VERSION 5.7 ;
BUSBITCHARS "[]" ;
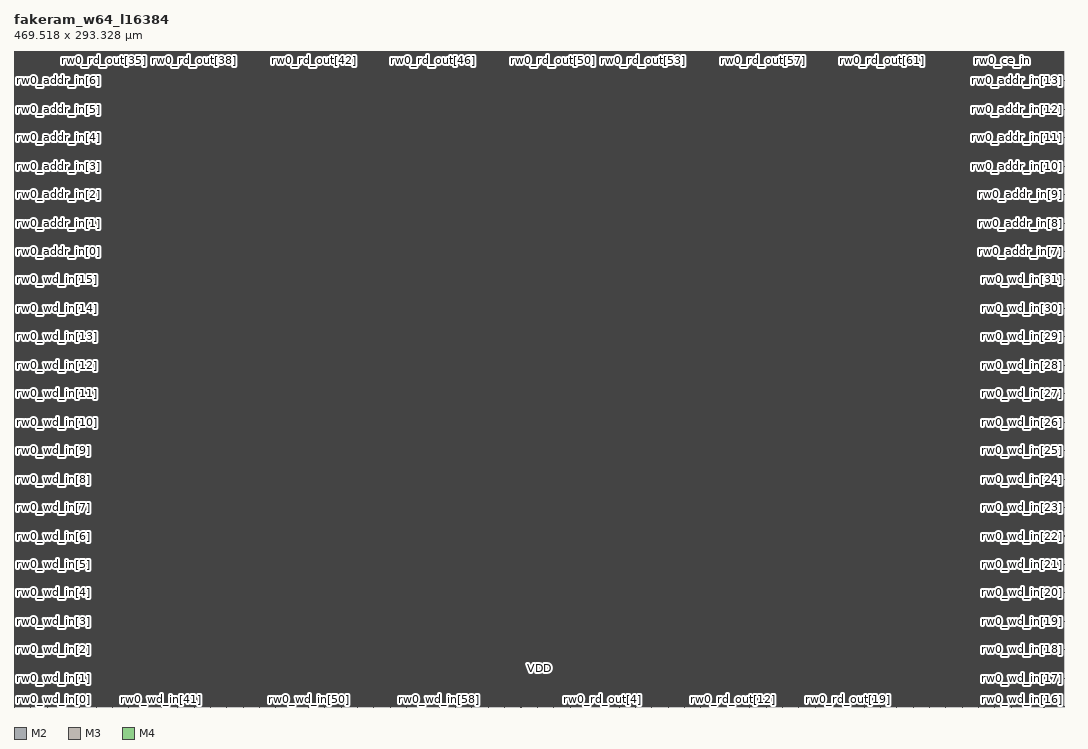
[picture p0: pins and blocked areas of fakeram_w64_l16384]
MACRO fakeram_w64_l16384
  FOREIGN fakeram_w64_l16384 0 0 ;
  SYMMETRY X Y R90 ;
  SIZE 469.518 BY 293.328 ;
  CLASS BLOCK ;
  PIN rw0_wd_in[0]
    DIRECTION INPUT ;
    USE SIGNAL ;
    SHAPE ABUTMENT ;
    PORT
      LAYER M2 ;
      RECT 0.000 0.138 0.036 0.150 ;
    END
  END rw0_wd_in[0]
  PIN rw0_wd_in[1]
    DIRECTION INPUT ;
    USE SIGNAL ;
    SHAPE ABUTMENT ;
    PORT
      LAYER M2 ;
      RECT 0.000 12.858 0.036 12.870 ;
    END
  END rw0_wd_in[1]
  PIN rw0_wd_in[2]
    DIRECTION INPUT ;
    USE SIGNAL ;
    SHAPE ABUTMENT ;
    PORT
      LAYER M2 ;
      RECT 0.000 25.578 0.036 25.590 ;
    END
  END rw0_wd_in[2]
  PIN rw0_wd_in[3]
    DIRECTION INPUT ;
    USE SIGNAL ;
    SHAPE ABUTMENT ;
    PORT
      LAYER M2 ;
      RECT 0.000 38.298 0.036 38.310 ;
    END
  END rw0_wd_in[3]
  PIN rw0_wd_in[4]
    DIRECTION INPUT ;
    USE SIGNAL ;
    SHAPE ABUTMENT ;
    PORT
      LAYER M2 ;
      RECT 0.000 51.018 0.036 51.030 ;
    END
  END rw0_wd_in[4]
  PIN rw0_wd_in[5]
    DIRECTION INPUT ;
    USE SIGNAL ;
    SHAPE ABUTMENT ;
    PORT
      LAYER M2 ;
      RECT 0.000 63.738 0.036 63.750 ;
    END
  END rw0_wd_in[5]
  PIN rw0_wd_in[6]
    DIRECTION INPUT ;
    USE SIGNAL ;
    SHAPE ABUTMENT ;
    PORT
      LAYER M2 ;
      RECT 0.000 76.458 0.036 76.470 ;
    END
  END rw0_wd_in[6]
  PIN rw0_wd_in[7]
    DIRECTION INPUT ;
    USE SIGNAL ;
    SHAPE ABUTMENT ;
    PORT
      LAYER M2 ;
      RECT 0.000 89.178 0.036 89.190 ;
    END
  END rw0_wd_in[7]
  PIN rw0_wd_in[8]
    DIRECTION INPUT ;
    USE SIGNAL ;
    SHAPE ABUTMENT ;
    PORT
      LAYER M2 ;
      RECT 0.000 101.898 0.036 101.910 ;
    END
  END rw0_wd_in[8]
  PIN rw0_wd_in[9]
    DIRECTION INPUT ;
    USE SIGNAL ;
    SHAPE ABUTMENT ;
    PORT
      LAYER M2 ;
      RECT 0.000 114.618 0.036 114.630 ;
    END
  END rw0_wd_in[9]
  PIN rw0_wd_in[10]
    DIRECTION INPUT ;
    USE SIGNAL ;
    SHAPE ABUTMENT ;
    PORT
      LAYER M2 ;
      RECT 0.000 127.338 0.036 127.350 ;
    END
  END rw0_wd_in[10]
  PIN rw0_wd_in[11]
    DIRECTION INPUT ;
    USE SIGNAL ;
    SHAPE ABUTMENT ;
    PORT
      LAYER M2 ;
      RECT 0.000 140.058 0.036 140.070 ;
    END
  END rw0_wd_in[11]
  PIN rw0_wd_in[12]
    DIRECTION INPUT ;
    USE SIGNAL ;
    SHAPE ABUTMENT ;
    PORT
      LAYER M2 ;
      RECT 0.000 152.778 0.036 152.790 ;
    END
  END rw0_wd_in[12]
  PIN rw0_wd_in[13]
    DIRECTION INPUT ;
    USE SIGNAL ;
    SHAPE ABUTMENT ;
    PORT
      LAYER M2 ;
      RECT 0.000 165.498 0.036 165.510 ;
    END
  END rw0_wd_in[13]
  PIN rw0_wd_in[14]
    DIRECTION INPUT ;
    USE SIGNAL ;
    SHAPE ABUTMENT ;
    PORT
      LAYER M2 ;
      RECT 0.000 178.218 0.036 178.230 ;
    END
  END rw0_wd_in[14]
  PIN rw0_wd_in[15]
    DIRECTION INPUT ;
    USE SIGNAL ;
    SHAPE ABUTMENT ;
    PORT
      LAYER M2 ;
      RECT 0.000 190.938 0.036 190.950 ;
    END
  END rw0_wd_in[15]
  PIN rw0_wd_in[16]
    DIRECTION INPUT ;
    USE SIGNAL ;
    SHAPE ABUTMENT ;
    PORT
      LAYER M2 ;
      RECT 469.482 0.138 469.518 0.150 ;
    END
  END rw0_wd_in[16]
  PIN rw0_wd_in[17]
    DIRECTION INPUT ;
    USE SIGNAL ;
    SHAPE ABUTMENT ;
    PORT
      LAYER M2 ;
      RECT 469.482 12.858 469.518 12.870 ;
    END
  END rw0_wd_in[17]
  PIN rw0_wd_in[18]
    DIRECTION INPUT ;
    USE SIGNAL ;
    SHAPE ABUTMENT ;
    PORT
      LAYER M2 ;
      RECT 469.482 25.578 469.518 25.590 ;
    END
  END rw0_wd_in[18]
  PIN rw0_wd_in[19]
    DIRECTION INPUT ;
    USE SIGNAL ;
    SHAPE ABUTMENT ;
    PORT
      LAYER M2 ;
      RECT 469.482 38.298 469.518 38.310 ;
    END
  END rw0_wd_in[19]
  PIN rw0_wd_in[20]
    DIRECTION INPUT ;
    USE SIGNAL ;
    SHAPE ABUTMENT ;
    PORT
      LAYER M2 ;
      RECT 469.482 51.018 469.518 51.030 ;
    END
  END rw0_wd_in[20]
  PIN rw0_wd_in[21]
    DIRECTION INPUT ;
    USE SIGNAL ;
    SHAPE ABUTMENT ;
    PORT
      LAYER M2 ;
      RECT 469.482 63.738 469.518 63.750 ;
    END
  END rw0_wd_in[21]
  PIN rw0_wd_in[22]
    DIRECTION INPUT ;
    USE SIGNAL ;
    SHAPE ABUTMENT ;
    PORT
      LAYER M2 ;
      RECT 469.482 76.458 469.518 76.470 ;
    END
  END rw0_wd_in[22]
  PIN rw0_wd_in[23]
    DIRECTION INPUT ;
    USE SIGNAL ;
    SHAPE ABUTMENT ;
    PORT
      LAYER M2 ;
      RECT 469.482 89.178 469.518 89.190 ;
    END
  END rw0_wd_in[23]
  PIN rw0_wd_in[24]
    DIRECTION INPUT ;
    USE SIGNAL ;
    SHAPE ABUTMENT ;
    PORT
      LAYER M2 ;
      RECT 469.482 101.898 469.518 101.910 ;
    END
  END rw0_wd_in[24]
  PIN rw0_wd_in[25]
    DIRECTION INPUT ;
    USE SIGNAL ;
    SHAPE ABUTMENT ;
    PORT
      LAYER M2 ;
      RECT 469.482 114.618 469.518 114.630 ;
    END
  END rw0_wd_in[25]
  PIN rw0_wd_in[26]
    DIRECTION INPUT ;
    USE SIGNAL ;
    SHAPE ABUTMENT ;
    PORT
      LAYER M2 ;
      RECT 469.482 127.338 469.518 127.350 ;
    END
  END rw0_wd_in[26]
  PIN rw0_wd_in[27]
    DIRECTION INPUT ;
    USE SIGNAL ;
    SHAPE ABUTMENT ;
    PORT
      LAYER M2 ;
      RECT 469.482 140.058 469.518 140.070 ;
    END
  END rw0_wd_in[27]
  PIN rw0_wd_in[28]
    DIRECTION INPUT ;
    USE SIGNAL ;
    SHAPE ABUTMENT ;
    PORT
      LAYER M2 ;
      RECT 469.482 152.778 469.518 152.790 ;
    END
  END rw0_wd_in[28]
  PIN rw0_wd_in[29]
    DIRECTION INPUT ;
    USE SIGNAL ;
    SHAPE ABUTMENT ;
    PORT
      LAYER M2 ;
      RECT 469.482 165.498 469.518 165.510 ;
    END
  END rw0_wd_in[29]
  PIN rw0_wd_in[30]
    DIRECTION INPUT ;
    USE SIGNAL ;
    SHAPE ABUTMENT ;
    PORT
      LAYER M2 ;
      RECT 469.482 178.218 469.518 178.230 ;
    END
  END rw0_wd_in[30]
  PIN rw0_wd_in[31]
    DIRECTION INPUT ;
    USE SIGNAL ;
    SHAPE ABUTMENT ;
    PORT
      LAYER M2 ;
      RECT 469.482 190.938 469.518 190.950 ;
    END
  END rw0_wd_in[31]
  PIN rw0_wd_in[32]
    DIRECTION INPUT ;
    USE SIGNAL ;
    SHAPE ABUTMENT ;
    PORT
      LAYER M3 ;
      RECT 0.161 0.000 0.175 0.042 ;
    END
  END rw0_wd_in[32]
  PIN rw0_wd_in[33]
    DIRECTION INPUT ;
    USE SIGNAL ;
    SHAPE ABUTMENT ;
    PORT
      LAYER M3 ;
      RECT 7.469 0.000 7.483 0.042 ;
    END
  END rw0_wd_in[33]
  PIN rw0_wd_in[34]
    DIRECTION INPUT ;
    USE SIGNAL ;
    SHAPE ABUTMENT ;
    PORT
      LAYER M3 ;
      RECT 14.777 0.000 14.791 0.042 ;
    END
  END rw0_wd_in[34]
  PIN rw0_wd_in[35]
    DIRECTION INPUT ;
    USE SIGNAL ;
    SHAPE ABUTMENT ;
    PORT
      LAYER M3 ;
      RECT 22.085 0.000 22.099 0.042 ;
    END
  END rw0_wd_in[35]
  PIN rw0_wd_in[36]
    DIRECTION INPUT ;
    USE SIGNAL ;
    SHAPE ABUTMENT ;
    PORT
      LAYER M3 ;
      RECT 29.393 0.000 29.407 0.042 ;
    END
  END rw0_wd_in[36]
  PIN rw0_wd_in[37]
    DIRECTION INPUT ;
    USE SIGNAL ;
    SHAPE ABUTMENT ;
    PORT
      LAYER M3 ;
      RECT 36.701 0.000 36.715 0.042 ;
    END
  END rw0_wd_in[37]
  PIN rw0_wd_in[38]
    DIRECTION INPUT ;
    USE SIGNAL ;
    SHAPE ABUTMENT ;
    PORT
      LAYER M3 ;
      RECT 44.009 0.000 44.023 0.042 ;
    END
  END rw0_wd_in[38]
  PIN rw0_wd_in[39]
    DIRECTION INPUT ;
    USE SIGNAL ;
    SHAPE ABUTMENT ;
    PORT
      LAYER M3 ;
      RECT 51.317 0.000 51.331 0.042 ;
    END
  END rw0_wd_in[39]
  PIN rw0_wd_in[40]
    DIRECTION INPUT ;
    USE SIGNAL ;
    SHAPE ABUTMENT ;
    PORT
      LAYER M3 ;
      RECT 58.625 0.000 58.639 0.042 ;
    END
  END rw0_wd_in[40]
  PIN rw0_wd_in[41]
    DIRECTION INPUT ;
    USE SIGNAL ;
    SHAPE ABUTMENT ;
    PORT
      LAYER M3 ;
      RECT 65.933 0.000 65.947 0.042 ;
    END
  END rw0_wd_in[41]
  PIN rw0_wd_in[42]
    DIRECTION INPUT ;
    USE SIGNAL ;
    SHAPE ABUTMENT ;
    PORT
      LAYER M3 ;
      RECT 73.241 0.000 73.255 0.042 ;
    END
  END rw0_wd_in[42]
  PIN rw0_wd_in[43]
    DIRECTION INPUT ;
    USE SIGNAL ;
    SHAPE ABUTMENT ;
    PORT
      LAYER M3 ;
      RECT 80.549 0.000 80.563 0.042 ;
    END
  END rw0_wd_in[43]
  PIN rw0_wd_in[44]
    DIRECTION INPUT ;
    USE SIGNAL ;
    SHAPE ABUTMENT ;
    PORT
      LAYER M3 ;
      RECT 87.857 0.000 87.871 0.042 ;
    END
  END rw0_wd_in[44]
  PIN rw0_wd_in[45]
    DIRECTION INPUT ;
    USE SIGNAL ;
    SHAPE ABUTMENT ;
    PORT
      LAYER M3 ;
      RECT 95.165 0.000 95.179 0.042 ;
    END
  END rw0_wd_in[45]
  PIN rw0_wd_in[46]
    DIRECTION INPUT ;
    USE SIGNAL ;
    SHAPE ABUTMENT ;
    PORT
      LAYER M3 ;
      RECT 102.473 0.000 102.487 0.042 ;
    END
  END rw0_wd_in[46]
  PIN rw0_wd_in[47]
    DIRECTION INPUT ;
    USE SIGNAL ;
    SHAPE ABUTMENT ;
    PORT
      LAYER M3 ;
      RECT 109.781 0.000 109.795 0.042 ;
    END
  END rw0_wd_in[47]
  PIN rw0_wd_in[48]
    DIRECTION INPUT ;
    USE SIGNAL ;
    SHAPE ABUTMENT ;
    PORT
      LAYER M3 ;
      RECT 117.089 0.000 117.103 0.042 ;
    END
  END rw0_wd_in[48]
  PIN rw0_wd_in[49]
    DIRECTION INPUT ;
    USE SIGNAL ;
    SHAPE ABUTMENT ;
    PORT
      LAYER M3 ;
      RECT 124.397 0.000 124.411 0.042 ;
    END
  END rw0_wd_in[49]
  PIN rw0_wd_in[50]
    DIRECTION INPUT ;
    USE SIGNAL ;
    SHAPE ABUTMENT ;
    PORT
      LAYER M3 ;
      RECT 131.705 0.000 131.719 0.042 ;
    END
  END rw0_wd_in[50]
  PIN rw0_wd_in[51]
    DIRECTION INPUT ;
    USE SIGNAL ;
    SHAPE ABUTMENT ;
    PORT
      LAYER M3 ;
      RECT 139.013 0.000 139.027 0.042 ;
    END
  END rw0_wd_in[51]
  PIN rw0_wd_in[52]
    DIRECTION INPUT ;
    USE SIGNAL ;
    SHAPE ABUTMENT ;
    PORT
      LAYER M3 ;
      RECT 146.321 0.000 146.335 0.042 ;
    END
  END rw0_wd_in[52]
  PIN rw0_wd_in[53]
    DIRECTION INPUT ;
    USE SIGNAL ;
    SHAPE ABUTMENT ;
    PORT
      LAYER M3 ;
      RECT 153.629 0.000 153.643 0.042 ;
    END
  END rw0_wd_in[53]
  PIN rw0_wd_in[54]
    DIRECTION INPUT ;
    USE SIGNAL ;
    SHAPE ABUTMENT ;
    PORT
      LAYER M3 ;
      RECT 160.937 0.000 160.951 0.042 ;
    END
  END rw0_wd_in[54]
  PIN rw0_wd_in[55]
    DIRECTION INPUT ;
    USE SIGNAL ;
    SHAPE ABUTMENT ;
    PORT
      LAYER M3 ;
      RECT 168.245 0.000 168.259 0.042 ;
    END
  END rw0_wd_in[55]
  PIN rw0_wd_in[56]
    DIRECTION INPUT ;
    USE SIGNAL ;
    SHAPE ABUTMENT ;
    PORT
      LAYER M3 ;
      RECT 175.553 0.000 175.567 0.042 ;
    END
  END rw0_wd_in[56]
  PIN rw0_wd_in[57]
    DIRECTION INPUT ;
    USE SIGNAL ;
    SHAPE ABUTMENT ;
    PORT
      LAYER M3 ;
      RECT 182.861 0.000 182.875 0.042 ;
    END
  END rw0_wd_in[57]
  PIN rw0_wd_in[58]
    DIRECTION INPUT ;
    USE SIGNAL ;
    SHAPE ABUTMENT ;
    PORT
      LAYER M3 ;
      RECT 190.169 0.000 190.183 0.042 ;
    END
  END rw0_wd_in[58]
  PIN rw0_wd_in[59]
    DIRECTION INPUT ;
    USE SIGNAL ;
    SHAPE ABUTMENT ;
    PORT
      LAYER M3 ;
      RECT 197.477 0.000 197.491 0.042 ;
    END
  END rw0_wd_in[59]
  PIN rw0_wd_in[60]
    DIRECTION INPUT ;
    USE SIGNAL ;
    SHAPE ABUTMENT ;
    PORT
      LAYER M3 ;
      RECT 204.785 0.000 204.799 0.042 ;
    END
  END rw0_wd_in[60]
  PIN rw0_wd_in[61]
    DIRECTION INPUT ;
    USE SIGNAL ;
    SHAPE ABUTMENT ;
    PORT
      LAYER M3 ;
      RECT 212.093 0.000 212.107 0.042 ;
    END
  END rw0_wd_in[61]
  PIN rw0_wd_in[62]
    DIRECTION INPUT ;
    USE SIGNAL ;
    SHAPE ABUTMENT ;
    PORT
      LAYER M3 ;
      RECT 219.401 0.000 219.415 0.042 ;
    END
  END rw0_wd_in[62]
  PIN rw0_wd_in[63]
    DIRECTION INPUT ;
    USE SIGNAL ;
    SHAPE ABUTMENT ;
    PORT
      LAYER M3 ;
      RECT 226.709 0.000 226.723 0.042 ;
    END
  END rw0_wd_in[63]
  PIN rw0_rd_out[0]
    DIRECTION OUTPUT ;
    USE SIGNAL ;
    SHAPE ABUTMENT ;
    PORT
      LAYER M3 ;
      RECT 234.017 0.000 234.031 0.042 ;
    END
  END rw0_rd_out[0]
  PIN rw0_rd_out[1]
    DIRECTION OUTPUT ;
    USE SIGNAL ;
    SHAPE ABUTMENT ;
    PORT
      LAYER M3 ;
      RECT 241.325 0.000 241.339 0.042 ;
    END
  END rw0_rd_out[1]
  PIN rw0_rd_out[2]
    DIRECTION OUTPUT ;
    USE SIGNAL ;
    SHAPE ABUTMENT ;
    PORT
      LAYER M3 ;
      RECT 248.633 0.000 248.647 0.042 ;
    END
  END rw0_rd_out[2]
  PIN rw0_rd_out[3]
    DIRECTION OUTPUT ;
    USE SIGNAL ;
    SHAPE ABUTMENT ;
    PORT
      LAYER M3 ;
      RECT 255.941 0.000 255.955 0.042 ;
    END
  END rw0_rd_out[3]
  PIN rw0_rd_out[4]
    DIRECTION OUTPUT ;
    USE SIGNAL ;
    SHAPE ABUTMENT ;
    PORT
      LAYER M3 ;
      RECT 263.249 0.000 263.263 0.042 ;
    END
  END rw0_rd_out[4]
  PIN rw0_rd_out[5]
    DIRECTION OUTPUT ;
    USE SIGNAL ;
    SHAPE ABUTMENT ;
    PORT
      LAYER M3 ;
      RECT 270.557 0.000 270.571 0.042 ;
    END
  END rw0_rd_out[5]
  PIN rw0_rd_out[6]
    DIRECTION OUTPUT ;
    USE SIGNAL ;
    SHAPE ABUTMENT ;
    PORT
      LAYER M3 ;
      RECT 277.865 0.000 277.879 0.042 ;
    END
  END rw0_rd_out[6]
  PIN rw0_rd_out[7]
    DIRECTION OUTPUT ;
    USE SIGNAL ;
    SHAPE ABUTMENT ;
    PORT
      LAYER M3 ;
      RECT 285.173 0.000 285.187 0.042 ;
    END
  END rw0_rd_out[7]
  PIN rw0_rd_out[8]
    DIRECTION OUTPUT ;
    USE SIGNAL ;
    SHAPE ABUTMENT ;
    PORT
      LAYER M3 ;
      RECT 292.481 0.000 292.495 0.042 ;
    END
  END rw0_rd_out[8]
  PIN rw0_rd_out[9]
    DIRECTION OUTPUT ;
    USE SIGNAL ;
    SHAPE ABUTMENT ;
    PORT
      LAYER M3 ;
      RECT 299.789 0.000 299.803 0.042 ;
    END
  END rw0_rd_out[9]
  PIN rw0_rd_out[10]
    DIRECTION OUTPUT ;
    USE SIGNAL ;
    SHAPE ABUTMENT ;
    PORT
      LAYER M3 ;
      RECT 307.097 0.000 307.111 0.042 ;
    END
  END rw0_rd_out[10]
  PIN rw0_rd_out[11]
    DIRECTION OUTPUT ;
    USE SIGNAL ;
    SHAPE ABUTMENT ;
    PORT
      LAYER M3 ;
      RECT 314.405 0.000 314.419 0.042 ;
    END
  END rw0_rd_out[11]
  PIN rw0_rd_out[12]
    DIRECTION OUTPUT ;
    USE SIGNAL ;
    SHAPE ABUTMENT ;
    PORT
      LAYER M3 ;
      RECT 321.713 0.000 321.727 0.042 ;
    END
  END rw0_rd_out[12]
  PIN rw0_rd_out[13]
    DIRECTION OUTPUT ;
    USE SIGNAL ;
    SHAPE ABUTMENT ;
    PORT
      LAYER M3 ;
      RECT 329.021 0.000 329.035 0.042 ;
    END
  END rw0_rd_out[13]
  PIN rw0_rd_out[14]
    DIRECTION OUTPUT ;
    USE SIGNAL ;
    SHAPE ABUTMENT ;
    PORT
      LAYER M3 ;
      RECT 336.329 0.000 336.343 0.042 ;
    END
  END rw0_rd_out[14]
  PIN rw0_rd_out[15]
    DIRECTION OUTPUT ;
    USE SIGNAL ;
    SHAPE ABUTMENT ;
    PORT
      LAYER M3 ;
      RECT 343.637 0.000 343.651 0.042 ;
    END
  END rw0_rd_out[15]
  PIN rw0_rd_out[16]
    DIRECTION OUTPUT ;
    USE SIGNAL ;
    SHAPE ABUTMENT ;
    PORT
      LAYER M3 ;
      RECT 350.945 0.000 350.959 0.042 ;
    END
  END rw0_rd_out[16]
  PIN rw0_rd_out[17]
    DIRECTION OUTPUT ;
    USE SIGNAL ;
    SHAPE ABUTMENT ;
    PORT
      LAYER M3 ;
      RECT 358.253 0.000 358.267 0.042 ;
    END
  END rw0_rd_out[17]
  PIN rw0_rd_out[18]
    DIRECTION OUTPUT ;
    USE SIGNAL ;
    SHAPE ABUTMENT ;
    PORT
      LAYER M3 ;
      RECT 365.561 0.000 365.575 0.042 ;
    END
  END rw0_rd_out[18]
  PIN rw0_rd_out[19]
    DIRECTION OUTPUT ;
    USE SIGNAL ;
    SHAPE ABUTMENT ;
    PORT
      LAYER M3 ;
      RECT 372.869 0.000 372.883 0.042 ;
    END
  END rw0_rd_out[19]
  PIN rw0_rd_out[20]
    DIRECTION OUTPUT ;
    USE SIGNAL ;
    SHAPE ABUTMENT ;
    PORT
      LAYER M3 ;
      RECT 380.177 0.000 380.191 0.042 ;
    END
  END rw0_rd_out[20]
  PIN rw0_rd_out[21]
    DIRECTION OUTPUT ;
    USE SIGNAL ;
    SHAPE ABUTMENT ;
    PORT
      LAYER M3 ;
      RECT 387.485 0.000 387.499 0.042 ;
    END
  END rw0_rd_out[21]
  PIN rw0_rd_out[22]
    DIRECTION OUTPUT ;
    USE SIGNAL ;
    SHAPE ABUTMENT ;
    PORT
      LAYER M3 ;
      RECT 394.793 0.000 394.807 0.042 ;
    END
  END rw0_rd_out[22]
  PIN rw0_rd_out[23]
    DIRECTION OUTPUT ;
    USE SIGNAL ;
    SHAPE ABUTMENT ;
    PORT
      LAYER M3 ;
      RECT 402.101 0.000 402.115 0.042 ;
    END
  END rw0_rd_out[23]
  PIN rw0_rd_out[24]
    DIRECTION OUTPUT ;
    USE SIGNAL ;
    SHAPE ABUTMENT ;
    PORT
      LAYER M3 ;
      RECT 409.409 0.000 409.423 0.042 ;
    END
  END rw0_rd_out[24]
  PIN rw0_rd_out[25]
    DIRECTION OUTPUT ;
    USE SIGNAL ;
    SHAPE ABUTMENT ;
    PORT
      LAYER M3 ;
      RECT 416.717 0.000 416.731 0.042 ;
    END
  END rw0_rd_out[25]
  PIN rw0_rd_out[26]
    DIRECTION OUTPUT ;
    USE SIGNAL ;
    SHAPE ABUTMENT ;
    PORT
      LAYER M3 ;
      RECT 424.025 0.000 424.039 0.042 ;
    END
  END rw0_rd_out[26]
  PIN rw0_rd_out[27]
    DIRECTION OUTPUT ;
    USE SIGNAL ;
    SHAPE ABUTMENT ;
    PORT
      LAYER M3 ;
      RECT 431.333 0.000 431.347 0.042 ;
    END
  END rw0_rd_out[27]
  PIN rw0_rd_out[28]
    DIRECTION OUTPUT ;
    USE SIGNAL ;
    SHAPE ABUTMENT ;
    PORT
      LAYER M3 ;
      RECT 438.641 0.000 438.655 0.042 ;
    END
  END rw0_rd_out[28]
  PIN rw0_rd_out[29]
    DIRECTION OUTPUT ;
    USE SIGNAL ;
    SHAPE ABUTMENT ;
    PORT
      LAYER M3 ;
      RECT 445.949 0.000 445.963 0.042 ;
    END
  END rw0_rd_out[29]
  PIN rw0_rd_out[30]
    DIRECTION OUTPUT ;
    USE SIGNAL ;
    SHAPE ABUTMENT ;
    PORT
      LAYER M3 ;
      RECT 453.257 0.000 453.271 0.042 ;
    END
  END rw0_rd_out[30]
  PIN rw0_rd_out[31]
    DIRECTION OUTPUT ;
    USE SIGNAL ;
    SHAPE ABUTMENT ;
    PORT
      LAYER M3 ;
      RECT 460.565 0.000 460.579 0.042 ;
    END
  END rw0_rd_out[31]
  PIN rw0_rd_out[32]
    DIRECTION OUTPUT ;
    USE SIGNAL ;
    SHAPE ABUTMENT ;
    PORT
      LAYER M3 ;
      RECT 0.161 293.286 0.175 293.328 ;
    END
  END rw0_rd_out[32]
  PIN rw0_rd_out[33]
    DIRECTION OUTPUT ;
    USE SIGNAL ;
    SHAPE ABUTMENT ;
    PORT
      LAYER M3 ;
      RECT 13.545 293.286 13.559 293.328 ;
    END
  END rw0_rd_out[33]
  PIN rw0_rd_out[34]
    DIRECTION OUTPUT ;
    USE SIGNAL ;
    SHAPE ABUTMENT ;
    PORT
      LAYER M3 ;
      RECT 26.929 293.286 26.943 293.328 ;
    END
  END rw0_rd_out[34]
  PIN rw0_rd_out[35]
    DIRECTION OUTPUT ;
    USE SIGNAL ;
    SHAPE ABUTMENT ;
    PORT
      LAYER M3 ;
      RECT 40.313 293.286 40.327 293.328 ;
    END
  END rw0_rd_out[35]
  PIN rw0_rd_out[36]
    DIRECTION OUTPUT ;
    USE SIGNAL ;
    SHAPE ABUTMENT ;
    PORT
      LAYER M3 ;
      RECT 53.697 293.286 53.711 293.328 ;
    END
  END rw0_rd_out[36]
  PIN rw0_rd_out[37]
    DIRECTION OUTPUT ;
    USE SIGNAL ;
    SHAPE ABUTMENT ;
    PORT
      LAYER M3 ;
      RECT 67.081 293.286 67.095 293.328 ;
    END
  END rw0_rd_out[37]
  PIN rw0_rd_out[38]
    DIRECTION OUTPUT ;
    USE SIGNAL ;
    SHAPE ABUTMENT ;
    PORT
      LAYER M3 ;
      RECT 80.465 293.286 80.479 293.328 ;
    END
  END rw0_rd_out[38]
  PIN rw0_rd_out[39]
    DIRECTION OUTPUT ;
    USE SIGNAL ;
    SHAPE ABUTMENT ;
    PORT
      LAYER M3 ;
      RECT 93.849 293.286 93.863 293.328 ;
    END
  END rw0_rd_out[39]
  PIN rw0_rd_out[40]
    DIRECTION OUTPUT ;
    USE SIGNAL ;
    SHAPE ABUTMENT ;
    PORT
      LAYER M3 ;
      RECT 107.233 293.286 107.247 293.328 ;
    END
  END rw0_rd_out[40]
  PIN rw0_rd_out[41]
    DIRECTION OUTPUT ;
    USE SIGNAL ;
    SHAPE ABUTMENT ;
    PORT
      LAYER M3 ;
      RECT 120.617 293.286 120.631 293.328 ;
    END
  END rw0_rd_out[41]
  PIN rw0_rd_out[42]
    DIRECTION OUTPUT ;
    USE SIGNAL ;
    SHAPE ABUTMENT ;
    PORT
      LAYER M3 ;
      RECT 134.001 293.286 134.015 293.328 ;
    END
  END rw0_rd_out[42]
  PIN rw0_rd_out[43]
    DIRECTION OUTPUT ;
    USE SIGNAL ;
    SHAPE ABUTMENT ;
    PORT
      LAYER M3 ;
      RECT 147.385 293.286 147.399 293.328 ;
    END
  END rw0_rd_out[43]
  PIN rw0_rd_out[44]
    DIRECTION OUTPUT ;
    USE SIGNAL ;
    SHAPE ABUTMENT ;
    PORT
      LAYER M3 ;
      RECT 160.769 293.286 160.783 293.328 ;
    END
  END rw0_rd_out[44]
  PIN rw0_rd_out[45]
    DIRECTION OUTPUT ;
    USE SIGNAL ;
    SHAPE ABUTMENT ;
    PORT
      LAYER M3 ;
      RECT 174.153 293.286 174.167 293.328 ;
    END
  END rw0_rd_out[45]
  PIN rw0_rd_out[46]
    DIRECTION OUTPUT ;
    USE SIGNAL ;
    SHAPE ABUTMENT ;
    PORT
      LAYER M3 ;
      RECT 187.537 293.286 187.551 293.328 ;
    END
  END rw0_rd_out[46]
  PIN rw0_rd_out[47]
    DIRECTION OUTPUT ;
    USE SIGNAL ;
    SHAPE ABUTMENT ;
    PORT
      LAYER M3 ;
      RECT 200.921 293.286 200.935 293.328 ;
    END
  END rw0_rd_out[47]
  PIN rw0_rd_out[48]
    DIRECTION OUTPUT ;
    USE SIGNAL ;
    SHAPE ABUTMENT ;
    PORT
      LAYER M3 ;
      RECT 214.305 293.286 214.319 293.328 ;
    END
  END rw0_rd_out[48]
  PIN rw0_rd_out[49]
    DIRECTION OUTPUT ;
    USE SIGNAL ;
    SHAPE ABUTMENT ;
    PORT
      LAYER M3 ;
      RECT 227.689 293.286 227.703 293.328 ;
    END
  END rw0_rd_out[49]
  PIN rw0_rd_out[50]
    DIRECTION OUTPUT ;
    USE SIGNAL ;
    SHAPE ABUTMENT ;
    PORT
      LAYER M3 ;
      RECT 241.073 293.286 241.087 293.328 ;
    END
  END rw0_rd_out[50]
  PIN rw0_rd_out[51]
    DIRECTION OUTPUT ;
    USE SIGNAL ;
    SHAPE ABUTMENT ;
    PORT
      LAYER M3 ;
      RECT 254.457 293.286 254.471 293.328 ;
    END
  END rw0_rd_out[51]
  PIN rw0_rd_out[52]
    DIRECTION OUTPUT ;
    USE SIGNAL ;
    SHAPE ABUTMENT ;
    PORT
      LAYER M3 ;
      RECT 267.841 293.286 267.855 293.328 ;
    END
  END rw0_rd_out[52]
  PIN rw0_rd_out[53]
    DIRECTION OUTPUT ;
    USE SIGNAL ;
    SHAPE ABUTMENT ;
    PORT
      LAYER M3 ;
      RECT 281.225 293.286 281.239 293.328 ;
    END
  END rw0_rd_out[53]
  PIN rw0_rd_out[54]
    DIRECTION OUTPUT ;
    USE SIGNAL ;
    SHAPE ABUTMENT ;
    PORT
      LAYER M3 ;
      RECT 294.609 293.286 294.623 293.328 ;
    END
  END rw0_rd_out[54]
  PIN rw0_rd_out[55]
    DIRECTION OUTPUT ;
    USE SIGNAL ;
    SHAPE ABUTMENT ;
    PORT
      LAYER M3 ;
      RECT 307.993 293.286 308.007 293.328 ;
    END
  END rw0_rd_out[55]
  PIN rw0_rd_out[56]
    DIRECTION OUTPUT ;
    USE SIGNAL ;
    SHAPE ABUTMENT ;
    PORT
      LAYER M3 ;
      RECT 321.377 293.286 321.391 293.328 ;
    END
  END rw0_rd_out[56]
  PIN rw0_rd_out[57]
    DIRECTION OUTPUT ;
    USE SIGNAL ;
    SHAPE ABUTMENT ;
    PORT
      LAYER M3 ;
      RECT 334.761 293.286 334.775 293.328 ;
    END
  END rw0_rd_out[57]
  PIN rw0_rd_out[58]
    DIRECTION OUTPUT ;
    USE SIGNAL ;
    SHAPE ABUTMENT ;
    PORT
      LAYER M3 ;
      RECT 348.145 293.286 348.159 293.328 ;
    END
  END rw0_rd_out[58]
  PIN rw0_rd_out[59]
    DIRECTION OUTPUT ;
    USE SIGNAL ;
    SHAPE ABUTMENT ;
    PORT
      LAYER M3 ;
      RECT 361.529 293.286 361.543 293.328 ;
    END
  END rw0_rd_out[59]
  PIN rw0_rd_out[60]
    DIRECTION OUTPUT ;
    USE SIGNAL ;
    SHAPE ABUTMENT ;
    PORT
      LAYER M3 ;
      RECT 374.913 293.286 374.927 293.328 ;
    END
  END rw0_rd_out[60]
  PIN rw0_rd_out[61]
    DIRECTION OUTPUT ;
    USE SIGNAL ;
    SHAPE ABUTMENT ;
    PORT
      LAYER M3 ;
      RECT 388.297 293.286 388.311 293.328 ;
    END
  END rw0_rd_out[61]
  PIN rw0_rd_out[62]
    DIRECTION OUTPUT ;
    USE SIGNAL ;
    SHAPE ABUTMENT ;
    PORT
      LAYER M3 ;
      RECT 401.681 293.286 401.695 293.328 ;
    END
  END rw0_rd_out[62]
  PIN rw0_rd_out[63]
    DIRECTION OUTPUT ;
    USE SIGNAL ;
    SHAPE ABUTMENT ;
    PORT
      LAYER M3 ;
      RECT 415.065 293.286 415.079 293.328 ;
    END
  END rw0_rd_out[63]
  PIN rw0_addr_in[0]
    DIRECTION INPUT ;
    USE SIGNAL ;
    SHAPE ABUTMENT ;
    PORT
      LAYER M2 ;
      RECT 0.000 203.658 0.036 203.670 ;
    END
  END rw0_addr_in[0]
  PIN rw0_addr_in[1]
    DIRECTION INPUT ;
    USE SIGNAL ;
    SHAPE ABUTMENT ;
    PORT
      LAYER M2 ;
      RECT 0.000 216.378 0.036 216.390 ;
    END
  END rw0_addr_in[1]
  PIN rw0_addr_in[2]
    DIRECTION INPUT ;
    USE SIGNAL ;
    SHAPE ABUTMENT ;
    PORT
      LAYER M2 ;
      RECT 0.000 229.098 0.036 229.110 ;
    END
  END rw0_addr_in[2]
  PIN rw0_addr_in[3]
    DIRECTION INPUT ;
    USE SIGNAL ;
    SHAPE ABUTMENT ;
    PORT
      LAYER M2 ;
      RECT 0.000 241.818 0.036 241.830 ;
    END
  END rw0_addr_in[3]
  PIN rw0_addr_in[4]
    DIRECTION INPUT ;
    USE SIGNAL ;
    SHAPE ABUTMENT ;
    PORT
      LAYER M2 ;
      RECT 0.000 254.538 0.036 254.550 ;
    END
  END rw0_addr_in[4]
  PIN rw0_addr_in[5]
    DIRECTION INPUT ;
    USE SIGNAL ;
    SHAPE ABUTMENT ;
    PORT
      LAYER M2 ;
      RECT 0.000 267.258 0.036 267.270 ;
    END
  END rw0_addr_in[5]
  PIN rw0_addr_in[6]
    DIRECTION INPUT ;
    USE SIGNAL ;
    SHAPE ABUTMENT ;
    PORT
      LAYER M2 ;
      RECT 0.000 279.978 0.036 279.990 ;
    END
  END rw0_addr_in[6]
  PIN rw0_addr_in[7]
    DIRECTION INPUT ;
    USE SIGNAL ;
    SHAPE ABUTMENT ;
    PORT
      LAYER M2 ;
      RECT 469.482 203.658 469.518 203.670 ;
    END
  END rw0_addr_in[7]
  PIN rw0_addr_in[8]
    DIRECTION INPUT ;
    USE SIGNAL ;
    SHAPE ABUTMENT ;
    PORT
      LAYER M2 ;
      RECT 469.482 216.378 469.518 216.390 ;
    END
  END rw0_addr_in[8]
  PIN rw0_addr_in[9]
    DIRECTION INPUT ;
    USE SIGNAL ;
    SHAPE ABUTMENT ;
    PORT
      LAYER M2 ;
      RECT 469.482 229.098 469.518 229.110 ;
    END
  END rw0_addr_in[9]
  PIN rw0_addr_in[10]
    DIRECTION INPUT ;
    USE SIGNAL ;
    SHAPE ABUTMENT ;
    PORT
      LAYER M2 ;
      RECT 469.482 241.818 469.518 241.830 ;
    END
  END rw0_addr_in[10]
  PIN rw0_addr_in[11]
    DIRECTION INPUT ;
    USE SIGNAL ;
    SHAPE ABUTMENT ;
    PORT
      LAYER M2 ;
      RECT 469.482 254.538 469.518 254.550 ;
    END
  END rw0_addr_in[11]
  PIN rw0_addr_in[12]
    DIRECTION INPUT ;
    USE SIGNAL ;
    SHAPE ABUTMENT ;
    PORT
      LAYER M2 ;
      RECT 469.482 267.258 469.518 267.270 ;
    END
  END rw0_addr_in[12]
  PIN rw0_addr_in[13]
    DIRECTION INPUT ;
    USE SIGNAL ;
    SHAPE ABUTMENT ;
    PORT
      LAYER M2 ;
      RECT 469.482 279.978 469.518 279.990 ;
    END
  END rw0_addr_in[13]
  PIN rw0_we_in
    DIRECTION INPUT ;
    USE SIGNAL ;
    SHAPE ABUTMENT ;
    PORT
      LAYER M3 ;
      RECT 428.449 293.286 428.463 293.328 ;
    END
  END rw0_we_in
  PIN rw0_ce_in
    DIRECTION INPUT ;
    USE SIGNAL ;
    SHAPE ABUTMENT ;
    PORT
      LAYER M3 ;
      RECT 441.833 293.286 441.847 293.328 ;
    END
  END rw0_ce_in
  PIN rw0_clk
    DIRECTION INPUT ;
    USE SIGNAL ;
    SHAPE ABUTMENT ;
    PORT
      LAYER M3 ;
      RECT 455.217 293.286 455.231 293.328 ;
    END
  END rw0_clk
  PIN VSS
    DIRECTION INOUT ;
    USE GROUND ;
    PORT
      LAYER M4 ;
      RECT 0.168 0.120 469.350 0.168 ;
      RECT 0.168 0.504 469.350 0.552 ;
      RECT 0.168 0.888 469.350 0.936 ;
      RECT 0.168 1.272 469.350 1.320 ;
      RECT 0.168 1.656 469.350 1.704 ;
      RECT 0.168 2.040 469.350 2.088 ;
      RECT 0.168 2.424 469.350 2.472 ;
      RECT 0.168 2.808 469.350 2.856 ;
      RECT 0.168 3.192 469.350 3.240 ;
      RECT 0.168 3.576 469.350 3.624 ;
      RECT 0.168 3.960 469.350 4.008 ;
      RECT 0.168 4.344 469.350 4.392 ;
      RECT 0.168 4.728 469.350 4.776 ;
      RECT 0.168 5.112 469.350 5.160 ;
      RECT 0.168 5.496 469.350 5.544 ;
      RECT 0.168 5.880 469.350 5.928 ;
      RECT 0.168 6.264 469.350 6.312 ;
      RECT 0.168 6.648 469.350 6.696 ;
      RECT 0.168 7.032 469.350 7.080 ;
      RECT 0.168 7.416 469.350 7.464 ;
      RECT 0.168 7.800 469.350 7.848 ;
      RECT 0.168 8.184 469.350 8.232 ;
      RECT 0.168 8.568 469.350 8.616 ;
      RECT 0.168 8.952 469.350 9.000 ;
      RECT 0.168 9.336 469.350 9.384 ;
      RECT 0.168 9.720 469.350 9.768 ;
      RECT 0.168 10.104 469.350 10.152 ;
      RECT 0.168 10.488 469.350 10.536 ;
      RECT 0.168 10.872 469.350 10.920 ;
      RECT 0.168 11.256 469.350 11.304 ;
      RECT 0.168 11.640 469.350 11.688 ;
      RECT 0.168 12.024 469.350 12.072 ;
      RECT 0.168 12.408 469.350 12.456 ;
      RECT 0.168 12.792 469.350 12.840 ;
      RECT 0.168 13.176 469.350 13.224 ;
      RECT 0.168 13.560 469.350 13.608 ;
      RECT 0.168 13.944 469.350 13.992 ;
      RECT 0.168 14.328 469.350 14.376 ;
      RECT 0.168 14.712 469.350 14.760 ;
      RECT 0.168 15.096 469.350 15.144 ;
      RECT 0.168 15.480 469.350 15.528 ;
      RECT 0.168 15.864 469.350 15.912 ;
      RECT 0.168 16.248 469.350 16.296 ;
      RECT 0.168 16.632 469.350 16.680 ;
      RECT 0.168 17.016 469.350 17.064 ;
      RECT 0.168 17.400 469.350 17.448 ;
      RECT 0.168 17.784 469.350 17.832 ;
      RECT 0.168 18.168 469.350 18.216 ;
      RECT 0.168 18.552 469.350 18.600 ;
      RECT 0.168 18.936 469.350 18.984 ;
      RECT 0.168 19.320 469.350 19.368 ;
      RECT 0.168 19.704 469.350 19.752 ;
      RECT 0.168 20.088 469.350 20.136 ;
      RECT 0.168 20.472 469.350 20.520 ;
      RECT 0.168 20.856 469.350 20.904 ;
      RECT 0.168 21.240 469.350 21.288 ;
      RECT 0.168 21.624 469.350 21.672 ;
      RECT 0.168 22.008 469.350 22.056 ;
      RECT 0.168 22.392 469.350 22.440 ;
      RECT 0.168 22.776 469.350 22.824 ;
      RECT 0.168 23.160 469.350 23.208 ;
      RECT 0.168 23.544 469.350 23.592 ;
      RECT 0.168 23.928 469.350 23.976 ;
      RECT 0.168 24.312 469.350 24.360 ;
      RECT 0.168 24.696 469.350 24.744 ;
      RECT 0.168 25.080 469.350 25.128 ;
      RECT 0.168 25.464 469.350 25.512 ;
      RECT 0.168 25.848 469.350 25.896 ;
      RECT 0.168 26.232 469.350 26.280 ;
      RECT 0.168 26.616 469.350 26.664 ;
      RECT 0.168 27.000 469.350 27.048 ;
      RECT 0.168 27.384 469.350 27.432 ;
      RECT 0.168 27.768 469.350 27.816 ;
      RECT 0.168 28.152 469.350 28.200 ;
      RECT 0.168 28.536 469.350 28.584 ;
      RECT 0.168 28.920 469.350 28.968 ;
      RECT 0.168 29.304 469.350 29.352 ;
      RECT 0.168 29.688 469.350 29.736 ;
      RECT 0.168 30.072 469.350 30.120 ;
      RECT 0.168 30.456 469.350 30.504 ;
      RECT 0.168 30.840 469.350 30.888 ;
      RECT 0.168 31.224 469.350 31.272 ;
      RECT 0.168 31.608 469.350 31.656 ;
      RECT 0.168 31.992 469.350 32.040 ;
      RECT 0.168 32.376 469.350 32.424 ;
      RECT 0.168 32.760 469.350 32.808 ;
      RECT 0.168 33.144 469.350 33.192 ;
      RECT 0.168 33.528 469.350 33.576 ;
      RECT 0.168 33.912 469.350 33.960 ;
      RECT 0.168 34.296 469.350 34.344 ;
      RECT 0.168 34.680 469.350 34.728 ;
      RECT 0.168 35.064 469.350 35.112 ;
      RECT 0.168 35.448 469.350 35.496 ;
      RECT 0.168 35.832 469.350 35.880 ;
      RECT 0.168 36.216 469.350 36.264 ;
      RECT 0.168 36.600 469.350 36.648 ;
      RECT 0.168 36.984 469.350 37.032 ;
      RECT 0.168 37.368 469.350 37.416 ;
      RECT 0.168 37.752 469.350 37.800 ;
      RECT 0.168 38.136 469.350 38.184 ;
      RECT 0.168 38.520 469.350 38.568 ;
      RECT 0.168 38.904 469.350 38.952 ;
      RECT 0.168 39.288 469.350 39.336 ;
      RECT 0.168 39.672 469.350 39.720 ;
      RECT 0.168 40.056 469.350 40.104 ;
      RECT 0.168 40.440 469.350 40.488 ;
      RECT 0.168 40.824 469.350 40.872 ;
      RECT 0.168 41.208 469.350 41.256 ;
      RECT 0.168 41.592 469.350 41.640 ;
      RECT 0.168 41.976 469.350 42.024 ;
      RECT 0.168 42.360 469.350 42.408 ;
      RECT 0.168 42.744 469.350 42.792 ;
      RECT 0.168 43.128 469.350 43.176 ;
      RECT 0.168 43.512 469.350 43.560 ;
      RECT 0.168 43.896 469.350 43.944 ;
      RECT 0.168 44.280 469.350 44.328 ;
      RECT 0.168 44.664 469.350 44.712 ;
      RECT 0.168 45.048 469.350 45.096 ;
      RECT 0.168 45.432 469.350 45.480 ;
      RECT 0.168 45.816 469.350 45.864 ;
      RECT 0.168 46.200 469.350 46.248 ;
      RECT 0.168 46.584 469.350 46.632 ;
      RECT 0.168 46.968 469.350 47.016 ;
      RECT 0.168 47.352 469.350 47.400 ;
      RECT 0.168 47.736 469.350 47.784 ;
      RECT 0.168 48.120 469.350 48.168 ;
      RECT 0.168 48.504 469.350 48.552 ;
      RECT 0.168 48.888 469.350 48.936 ;
      RECT 0.168 49.272 469.350 49.320 ;
      RECT 0.168 49.656 469.350 49.704 ;
      RECT 0.168 50.040 469.350 50.088 ;
      RECT 0.168 50.424 469.350 50.472 ;
      RECT 0.168 50.808 469.350 50.856 ;
      RECT 0.168 51.192 469.350 51.240 ;
      RECT 0.168 51.576 469.350 51.624 ;
      RECT 0.168 51.960 469.350 52.008 ;
      RECT 0.168 52.344 469.350 52.392 ;
      RECT 0.168 52.728 469.350 52.776 ;
      RECT 0.168 53.112 469.350 53.160 ;
      RECT 0.168 53.496 469.350 53.544 ;
      RECT 0.168 53.880 469.350 53.928 ;
      RECT 0.168 54.264 469.350 54.312 ;
      RECT 0.168 54.648 469.350 54.696 ;
      RECT 0.168 55.032 469.350 55.080 ;
      RECT 0.168 55.416 469.350 55.464 ;
      RECT 0.168 55.800 469.350 55.848 ;
      RECT 0.168 56.184 469.350 56.232 ;
      RECT 0.168 56.568 469.350 56.616 ;
      RECT 0.168 56.952 469.350 57.000 ;
      RECT 0.168 57.336 469.350 57.384 ;
      RECT 0.168 57.720 469.350 57.768 ;
      RECT 0.168 58.104 469.350 58.152 ;
      RECT 0.168 58.488 469.350 58.536 ;
      RECT 0.168 58.872 469.350 58.920 ;
      RECT 0.168 59.256 469.350 59.304 ;
      RECT 0.168 59.640 469.350 59.688 ;
      RECT 0.168 60.024 469.350 60.072 ;
      RECT 0.168 60.408 469.350 60.456 ;
      RECT 0.168 60.792 469.350 60.840 ;
      RECT 0.168 61.176 469.350 61.224 ;
      RECT 0.168 61.560 469.350 61.608 ;
      RECT 0.168 61.944 469.350 61.992 ;
      RECT 0.168 62.328 469.350 62.376 ;
      RECT 0.168 62.712 469.350 62.760 ;
      RECT 0.168 63.096 469.350 63.144 ;
      RECT 0.168 63.480 469.350 63.528 ;
      RECT 0.168 63.864 469.350 63.912 ;
      RECT 0.168 64.248 469.350 64.296 ;
      RECT 0.168 64.632 469.350 64.680 ;
      RECT 0.168 65.016 469.350 65.064 ;
      RECT 0.168 65.400 469.350 65.448 ;
      RECT 0.168 65.784 469.350 65.832 ;
      RECT 0.168 66.168 469.350 66.216 ;
      RECT 0.168 66.552 469.350 66.600 ;
      RECT 0.168 66.936 469.350 66.984 ;
      RECT 0.168 67.320 469.350 67.368 ;
      RECT 0.168 67.704 469.350 67.752 ;
      RECT 0.168 68.088 469.350 68.136 ;
      RECT 0.168 68.472 469.350 68.520 ;
      RECT 0.168 68.856 469.350 68.904 ;
      RECT 0.168 69.240 469.350 69.288 ;
      RECT 0.168 69.624 469.350 69.672 ;
      RECT 0.168 70.008 469.350 70.056 ;
      RECT 0.168 70.392 469.350 70.440 ;
      RECT 0.168 70.776 469.350 70.824 ;
      RECT 0.168 71.160 469.350 71.208 ;
      RECT 0.168 71.544 469.350 71.592 ;
      RECT 0.168 71.928 469.350 71.976 ;
      RECT 0.168 72.312 469.350 72.360 ;
      RECT 0.168 72.696 469.350 72.744 ;
      RECT 0.168 73.080 469.350 73.128 ;
      RECT 0.168 73.464 469.350 73.512 ;
      RECT 0.168 73.848 469.350 73.896 ;
      RECT 0.168 74.232 469.350 74.280 ;
      RECT 0.168 74.616 469.350 74.664 ;
      RECT 0.168 75.000 469.350 75.048 ;
      RECT 0.168 75.384 469.350 75.432 ;
      RECT 0.168 75.768 469.350 75.816 ;
      RECT 0.168 76.152 469.350 76.200 ;
      RECT 0.168 76.536 469.350 76.584 ;
      RECT 0.168 76.920 469.350 76.968 ;
      RECT 0.168 77.304 469.350 77.352 ;
      RECT 0.168 77.688 469.350 77.736 ;
      RECT 0.168 78.072 469.350 78.120 ;
      RECT 0.168 78.456 469.350 78.504 ;
      RECT 0.168 78.840 469.350 78.888 ;
      RECT 0.168 79.224 469.350 79.272 ;
      RECT 0.168 79.608 469.350 79.656 ;
      RECT 0.168 79.992 469.350 80.040 ;
      RECT 0.168 80.376 469.350 80.424 ;
      RECT 0.168 80.760 469.350 80.808 ;
      RECT 0.168 81.144 469.350 81.192 ;
      RECT 0.168 81.528 469.350 81.576 ;
      RECT 0.168 81.912 469.350 81.960 ;
      RECT 0.168 82.296 469.350 82.344 ;
      RECT 0.168 82.680 469.350 82.728 ;
      RECT 0.168 83.064 469.350 83.112 ;
      RECT 0.168 83.448 469.350 83.496 ;
      RECT 0.168 83.832 469.350 83.880 ;
      RECT 0.168 84.216 469.350 84.264 ;
      RECT 0.168 84.600 469.350 84.648 ;
      RECT 0.168 84.984 469.350 85.032 ;
      RECT 0.168 85.368 469.350 85.416 ;
      RECT 0.168 85.752 469.350 85.800 ;
      RECT 0.168 86.136 469.350 86.184 ;
      RECT 0.168 86.520 469.350 86.568 ;
      RECT 0.168 86.904 469.350 86.952 ;
      RECT 0.168 87.288 469.350 87.336 ;
      RECT 0.168 87.672 469.350 87.720 ;
      RECT 0.168 88.056 469.350 88.104 ;
      RECT 0.168 88.440 469.350 88.488 ;
      RECT 0.168 88.824 469.350 88.872 ;
      RECT 0.168 89.208 469.350 89.256 ;
      RECT 0.168 89.592 469.350 89.640 ;
      RECT 0.168 89.976 469.350 90.024 ;
      RECT 0.168 90.360 469.350 90.408 ;
      RECT 0.168 90.744 469.350 90.792 ;
      RECT 0.168 91.128 469.350 91.176 ;
      RECT 0.168 91.512 469.350 91.560 ;
      RECT 0.168 91.896 469.350 91.944 ;
      RECT 0.168 92.280 469.350 92.328 ;
      RECT 0.168 92.664 469.350 92.712 ;
      RECT 0.168 93.048 469.350 93.096 ;
      RECT 0.168 93.432 469.350 93.480 ;
      RECT 0.168 93.816 469.350 93.864 ;
      RECT 0.168 94.200 469.350 94.248 ;
      RECT 0.168 94.584 469.350 94.632 ;
      RECT 0.168 94.968 469.350 95.016 ;
      RECT 0.168 95.352 469.350 95.400 ;
      RECT 0.168 95.736 469.350 95.784 ;
      RECT 0.168 96.120 469.350 96.168 ;
      RECT 0.168 96.504 469.350 96.552 ;
      RECT 0.168 96.888 469.350 96.936 ;
      RECT 0.168 97.272 469.350 97.320 ;
      RECT 0.168 97.656 469.350 97.704 ;
      RECT 0.168 98.040 469.350 98.088 ;
      RECT 0.168 98.424 469.350 98.472 ;
      RECT 0.168 98.808 469.350 98.856 ;
      RECT 0.168 99.192 469.350 99.240 ;
      RECT 0.168 99.576 469.350 99.624 ;
      RECT 0.168 99.960 469.350 100.008 ;
      RECT 0.168 100.344 469.350 100.392 ;
      RECT 0.168 100.728 469.350 100.776 ;
      RECT 0.168 101.112 469.350 101.160 ;
      RECT 0.168 101.496 469.350 101.544 ;
      RECT 0.168 101.880 469.350 101.928 ;
      RECT 0.168 102.264 469.350 102.312 ;
      RECT 0.168 102.648 469.350 102.696 ;
      RECT 0.168 103.032 469.350 103.080 ;
      RECT 0.168 103.416 469.350 103.464 ;
      RECT 0.168 103.800 469.350 103.848 ;
      RECT 0.168 104.184 469.350 104.232 ;
      RECT 0.168 104.568 469.350 104.616 ;
      RECT 0.168 104.952 469.350 105.000 ;
      RECT 0.168 105.336 469.350 105.384 ;
      RECT 0.168 105.720 469.350 105.768 ;
      RECT 0.168 106.104 469.350 106.152 ;
      RECT 0.168 106.488 469.350 106.536 ;
      RECT 0.168 106.872 469.350 106.920 ;
      RECT 0.168 107.256 469.350 107.304 ;
      RECT 0.168 107.640 469.350 107.688 ;
      RECT 0.168 108.024 469.350 108.072 ;
      RECT 0.168 108.408 469.350 108.456 ;
      RECT 0.168 108.792 469.350 108.840 ;
      RECT 0.168 109.176 469.350 109.224 ;
      RECT 0.168 109.560 469.350 109.608 ;
      RECT 0.168 109.944 469.350 109.992 ;
      RECT 0.168 110.328 469.350 110.376 ;
      RECT 0.168 110.712 469.350 110.760 ;
      RECT 0.168 111.096 469.350 111.144 ;
      RECT 0.168 111.480 469.350 111.528 ;
      RECT 0.168 111.864 469.350 111.912 ;
      RECT 0.168 112.248 469.350 112.296 ;
      RECT 0.168 112.632 469.350 112.680 ;
      RECT 0.168 113.016 469.350 113.064 ;
      RECT 0.168 113.400 469.350 113.448 ;
      RECT 0.168 113.784 469.350 113.832 ;
      RECT 0.168 114.168 469.350 114.216 ;
      RECT 0.168 114.552 469.350 114.600 ;
      RECT 0.168 114.936 469.350 114.984 ;
      RECT 0.168 115.320 469.350 115.368 ;
      RECT 0.168 115.704 469.350 115.752 ;
      RECT 0.168 116.088 469.350 116.136 ;
      RECT 0.168 116.472 469.350 116.520 ;
      RECT 0.168 116.856 469.350 116.904 ;
      RECT 0.168 117.240 469.350 117.288 ;
      RECT 0.168 117.624 469.350 117.672 ;
      RECT 0.168 118.008 469.350 118.056 ;
      RECT 0.168 118.392 469.350 118.440 ;
      RECT 0.168 118.776 469.350 118.824 ;
      RECT 0.168 119.160 469.350 119.208 ;
      RECT 0.168 119.544 469.350 119.592 ;
      RECT 0.168 119.928 469.350 119.976 ;
      RECT 0.168 120.312 469.350 120.360 ;
      RECT 0.168 120.696 469.350 120.744 ;
      RECT 0.168 121.080 469.350 121.128 ;
      RECT 0.168 121.464 469.350 121.512 ;
      RECT 0.168 121.848 469.350 121.896 ;
      RECT 0.168 122.232 469.350 122.280 ;
      RECT 0.168 122.616 469.350 122.664 ;
      RECT 0.168 123.000 469.350 123.048 ;
      RECT 0.168 123.384 469.350 123.432 ;
      RECT 0.168 123.768 469.350 123.816 ;
      RECT 0.168 124.152 469.350 124.200 ;
      RECT 0.168 124.536 469.350 124.584 ;
      RECT 0.168 124.920 469.350 124.968 ;
      RECT 0.168 125.304 469.350 125.352 ;
      RECT 0.168 125.688 469.350 125.736 ;
      RECT 0.168 126.072 469.350 126.120 ;
      RECT 0.168 126.456 469.350 126.504 ;
      RECT 0.168 126.840 469.350 126.888 ;
      RECT 0.168 127.224 469.350 127.272 ;
      RECT 0.168 127.608 469.350 127.656 ;
      RECT 0.168 127.992 469.350 128.040 ;
      RECT 0.168 128.376 469.350 128.424 ;
      RECT 0.168 128.760 469.350 128.808 ;
      RECT 0.168 129.144 469.350 129.192 ;
      RECT 0.168 129.528 469.350 129.576 ;
      RECT 0.168 129.912 469.350 129.960 ;
      RECT 0.168 130.296 469.350 130.344 ;
      RECT 0.168 130.680 469.350 130.728 ;
      RECT 0.168 131.064 469.350 131.112 ;
      RECT 0.168 131.448 469.350 131.496 ;
      RECT 0.168 131.832 469.350 131.880 ;
      RECT 0.168 132.216 469.350 132.264 ;
      RECT 0.168 132.600 469.350 132.648 ;
      RECT 0.168 132.984 469.350 133.032 ;
      RECT 0.168 133.368 469.350 133.416 ;
      RECT 0.168 133.752 469.350 133.800 ;
      RECT 0.168 134.136 469.350 134.184 ;
      RECT 0.168 134.520 469.350 134.568 ;
      RECT 0.168 134.904 469.350 134.952 ;
      RECT 0.168 135.288 469.350 135.336 ;
      RECT 0.168 135.672 469.350 135.720 ;
      RECT 0.168 136.056 469.350 136.104 ;
      RECT 0.168 136.440 469.350 136.488 ;
      RECT 0.168 136.824 469.350 136.872 ;
      RECT 0.168 137.208 469.350 137.256 ;
      RECT 0.168 137.592 469.350 137.640 ;
      RECT 0.168 137.976 469.350 138.024 ;
      RECT 0.168 138.360 469.350 138.408 ;
      RECT 0.168 138.744 469.350 138.792 ;
      RECT 0.168 139.128 469.350 139.176 ;
      RECT 0.168 139.512 469.350 139.560 ;
      RECT 0.168 139.896 469.350 139.944 ;
      RECT 0.168 140.280 469.350 140.328 ;
      RECT 0.168 140.664 469.350 140.712 ;
      RECT 0.168 141.048 469.350 141.096 ;
      RECT 0.168 141.432 469.350 141.480 ;
      RECT 0.168 141.816 469.350 141.864 ;
      RECT 0.168 142.200 469.350 142.248 ;
      RECT 0.168 142.584 469.350 142.632 ;
      RECT 0.168 142.968 469.350 143.016 ;
      RECT 0.168 143.352 469.350 143.400 ;
      RECT 0.168 143.736 469.350 143.784 ;
      RECT 0.168 144.120 469.350 144.168 ;
      RECT 0.168 144.504 469.350 144.552 ;
      RECT 0.168 144.888 469.350 144.936 ;
      RECT 0.168 145.272 469.350 145.320 ;
      RECT 0.168 145.656 469.350 145.704 ;
      RECT 0.168 146.040 469.350 146.088 ;
      RECT 0.168 146.424 469.350 146.472 ;
      RECT 0.168 146.808 469.350 146.856 ;
      RECT 0.168 147.192 469.350 147.240 ;
      RECT 0.168 147.576 469.350 147.624 ;
      RECT 0.168 147.960 469.350 148.008 ;
      RECT 0.168 148.344 469.350 148.392 ;
      RECT 0.168 148.728 469.350 148.776 ;
      RECT 0.168 149.112 469.350 149.160 ;
      RECT 0.168 149.496 469.350 149.544 ;
      RECT 0.168 149.880 469.350 149.928 ;
      RECT 0.168 150.264 469.350 150.312 ;
      RECT 0.168 150.648 469.350 150.696 ;
      RECT 0.168 151.032 469.350 151.080 ;
      RECT 0.168 151.416 469.350 151.464 ;
      RECT 0.168 151.800 469.350 151.848 ;
      RECT 0.168 152.184 469.350 152.232 ;
      RECT 0.168 152.568 469.350 152.616 ;
      RECT 0.168 152.952 469.350 153.000 ;
      RECT 0.168 153.336 469.350 153.384 ;
      RECT 0.168 153.720 469.350 153.768 ;
      RECT 0.168 154.104 469.350 154.152 ;
      RECT 0.168 154.488 469.350 154.536 ;
      RECT 0.168 154.872 469.350 154.920 ;
      RECT 0.168 155.256 469.350 155.304 ;
      RECT 0.168 155.640 469.350 155.688 ;
      RECT 0.168 156.024 469.350 156.072 ;
      RECT 0.168 156.408 469.350 156.456 ;
      RECT 0.168 156.792 469.350 156.840 ;
      RECT 0.168 157.176 469.350 157.224 ;
      RECT 0.168 157.560 469.350 157.608 ;
      RECT 0.168 157.944 469.350 157.992 ;
      RECT 0.168 158.328 469.350 158.376 ;
      RECT 0.168 158.712 469.350 158.760 ;
      RECT 0.168 159.096 469.350 159.144 ;
      RECT 0.168 159.480 469.350 159.528 ;
      RECT 0.168 159.864 469.350 159.912 ;
      RECT 0.168 160.248 469.350 160.296 ;
      RECT 0.168 160.632 469.350 160.680 ;
      RECT 0.168 161.016 469.350 161.064 ;
      RECT 0.168 161.400 469.350 161.448 ;
      RECT 0.168 161.784 469.350 161.832 ;
      RECT 0.168 162.168 469.350 162.216 ;
      RECT 0.168 162.552 469.350 162.600 ;
      RECT 0.168 162.936 469.350 162.984 ;
      RECT 0.168 163.320 469.350 163.368 ;
      RECT 0.168 163.704 469.350 163.752 ;
      RECT 0.168 164.088 469.350 164.136 ;
      RECT 0.168 164.472 469.350 164.520 ;
      RECT 0.168 164.856 469.350 164.904 ;
      RECT 0.168 165.240 469.350 165.288 ;
      RECT 0.168 165.624 469.350 165.672 ;
      RECT 0.168 166.008 469.350 166.056 ;
      RECT 0.168 166.392 469.350 166.440 ;
      RECT 0.168 166.776 469.350 166.824 ;
      RECT 0.168 167.160 469.350 167.208 ;
      RECT 0.168 167.544 469.350 167.592 ;
      RECT 0.168 167.928 469.350 167.976 ;
      RECT 0.168 168.312 469.350 168.360 ;
      RECT 0.168 168.696 469.350 168.744 ;
      RECT 0.168 169.080 469.350 169.128 ;
      RECT 0.168 169.464 469.350 169.512 ;
      RECT 0.168 169.848 469.350 169.896 ;
      RECT 0.168 170.232 469.350 170.280 ;
      RECT 0.168 170.616 469.350 170.664 ;
      RECT 0.168 171.000 469.350 171.048 ;
      RECT 0.168 171.384 469.350 171.432 ;
      RECT 0.168 171.768 469.350 171.816 ;
      RECT 0.168 172.152 469.350 172.200 ;
      RECT 0.168 172.536 469.350 172.584 ;
      RECT 0.168 172.920 469.350 172.968 ;
      RECT 0.168 173.304 469.350 173.352 ;
      RECT 0.168 173.688 469.350 173.736 ;
      RECT 0.168 174.072 469.350 174.120 ;
      RECT 0.168 174.456 469.350 174.504 ;
      RECT 0.168 174.840 469.350 174.888 ;
      RECT 0.168 175.224 469.350 175.272 ;
      RECT 0.168 175.608 469.350 175.656 ;
      RECT 0.168 175.992 469.350 176.040 ;
      RECT 0.168 176.376 469.350 176.424 ;
      RECT 0.168 176.760 469.350 176.808 ;
      RECT 0.168 177.144 469.350 177.192 ;
      RECT 0.168 177.528 469.350 177.576 ;
      RECT 0.168 177.912 469.350 177.960 ;
      RECT 0.168 178.296 469.350 178.344 ;
      RECT 0.168 178.680 469.350 178.728 ;
      RECT 0.168 179.064 469.350 179.112 ;
      RECT 0.168 179.448 469.350 179.496 ;
      RECT 0.168 179.832 469.350 179.880 ;
      RECT 0.168 180.216 469.350 180.264 ;
      RECT 0.168 180.600 469.350 180.648 ;
      RECT 0.168 180.984 469.350 181.032 ;
      RECT 0.168 181.368 469.350 181.416 ;
      RECT 0.168 181.752 469.350 181.800 ;
      RECT 0.168 182.136 469.350 182.184 ;
      RECT 0.168 182.520 469.350 182.568 ;
      RECT 0.168 182.904 469.350 182.952 ;
      RECT 0.168 183.288 469.350 183.336 ;
      RECT 0.168 183.672 469.350 183.720 ;
      RECT 0.168 184.056 469.350 184.104 ;
      RECT 0.168 184.440 469.350 184.488 ;
      RECT 0.168 184.824 469.350 184.872 ;
      RECT 0.168 185.208 469.350 185.256 ;
      RECT 0.168 185.592 469.350 185.640 ;
      RECT 0.168 185.976 469.350 186.024 ;
      RECT 0.168 186.360 469.350 186.408 ;
      RECT 0.168 186.744 469.350 186.792 ;
      RECT 0.168 187.128 469.350 187.176 ;
      RECT 0.168 187.512 469.350 187.560 ;
      RECT 0.168 187.896 469.350 187.944 ;
      RECT 0.168 188.280 469.350 188.328 ;
      RECT 0.168 188.664 469.350 188.712 ;
      RECT 0.168 189.048 469.350 189.096 ;
      RECT 0.168 189.432 469.350 189.480 ;
      RECT 0.168 189.816 469.350 189.864 ;
      RECT 0.168 190.200 469.350 190.248 ;
      RECT 0.168 190.584 469.350 190.632 ;
      RECT 0.168 190.968 469.350 191.016 ;
      RECT 0.168 191.352 469.350 191.400 ;
      RECT 0.168 191.736 469.350 191.784 ;
      RECT 0.168 192.120 469.350 192.168 ;
      RECT 0.168 192.504 469.350 192.552 ;
      RECT 0.168 192.888 469.350 192.936 ;
      RECT 0.168 193.272 469.350 193.320 ;
      RECT 0.168 193.656 469.350 193.704 ;
      RECT 0.168 194.040 469.350 194.088 ;
      RECT 0.168 194.424 469.350 194.472 ;
      RECT 0.168 194.808 469.350 194.856 ;
      RECT 0.168 195.192 469.350 195.240 ;
      RECT 0.168 195.576 469.350 195.624 ;
      RECT 0.168 195.960 469.350 196.008 ;
      RECT 0.168 196.344 469.350 196.392 ;
      RECT 0.168 196.728 469.350 196.776 ;
      RECT 0.168 197.112 469.350 197.160 ;
      RECT 0.168 197.496 469.350 197.544 ;
      RECT 0.168 197.880 469.350 197.928 ;
      RECT 0.168 198.264 469.350 198.312 ;
      RECT 0.168 198.648 469.350 198.696 ;
      RECT 0.168 199.032 469.350 199.080 ;
      RECT 0.168 199.416 469.350 199.464 ;
      RECT 0.168 199.800 469.350 199.848 ;
      RECT 0.168 200.184 469.350 200.232 ;
      RECT 0.168 200.568 469.350 200.616 ;
      RECT 0.168 200.952 469.350 201.000 ;
      RECT 0.168 201.336 469.350 201.384 ;
      RECT 0.168 201.720 469.350 201.768 ;
      RECT 0.168 202.104 469.350 202.152 ;
      RECT 0.168 202.488 469.350 202.536 ;
      RECT 0.168 202.872 469.350 202.920 ;
      RECT 0.168 203.256 469.350 203.304 ;
      RECT 0.168 203.640 469.350 203.688 ;
      RECT 0.168 204.024 469.350 204.072 ;
      RECT 0.168 204.408 469.350 204.456 ;
      RECT 0.168 204.792 469.350 204.840 ;
      RECT 0.168 205.176 469.350 205.224 ;
      RECT 0.168 205.560 469.350 205.608 ;
      RECT 0.168 205.944 469.350 205.992 ;
      RECT 0.168 206.328 469.350 206.376 ;
      RECT 0.168 206.712 469.350 206.760 ;
      RECT 0.168 207.096 469.350 207.144 ;
      RECT 0.168 207.480 469.350 207.528 ;
      RECT 0.168 207.864 469.350 207.912 ;
      RECT 0.168 208.248 469.350 208.296 ;
      RECT 0.168 208.632 469.350 208.680 ;
      RECT 0.168 209.016 469.350 209.064 ;
      RECT 0.168 209.400 469.350 209.448 ;
      RECT 0.168 209.784 469.350 209.832 ;
      RECT 0.168 210.168 469.350 210.216 ;
      RECT 0.168 210.552 469.350 210.600 ;
      RECT 0.168 210.936 469.350 210.984 ;
      RECT 0.168 211.320 469.350 211.368 ;
      RECT 0.168 211.704 469.350 211.752 ;
      RECT 0.168 212.088 469.350 212.136 ;
      RECT 0.168 212.472 469.350 212.520 ;
      RECT 0.168 212.856 469.350 212.904 ;
      RECT 0.168 213.240 469.350 213.288 ;
      RECT 0.168 213.624 469.350 213.672 ;
      RECT 0.168 214.008 469.350 214.056 ;
      RECT 0.168 214.392 469.350 214.440 ;
      RECT 0.168 214.776 469.350 214.824 ;
      RECT 0.168 215.160 469.350 215.208 ;
      RECT 0.168 215.544 469.350 215.592 ;
      RECT 0.168 215.928 469.350 215.976 ;
      RECT 0.168 216.312 469.350 216.360 ;
      RECT 0.168 216.696 469.350 216.744 ;
      RECT 0.168 217.080 469.350 217.128 ;
      RECT 0.168 217.464 469.350 217.512 ;
      RECT 0.168 217.848 469.350 217.896 ;
      RECT 0.168 218.232 469.350 218.280 ;
      RECT 0.168 218.616 469.350 218.664 ;
      RECT 0.168 219.000 469.350 219.048 ;
      RECT 0.168 219.384 469.350 219.432 ;
      RECT 0.168 219.768 469.350 219.816 ;
      RECT 0.168 220.152 469.350 220.200 ;
      RECT 0.168 220.536 469.350 220.584 ;
      RECT 0.168 220.920 469.350 220.968 ;
      RECT 0.168 221.304 469.350 221.352 ;
      RECT 0.168 221.688 469.350 221.736 ;
      RECT 0.168 222.072 469.350 222.120 ;
      RECT 0.168 222.456 469.350 222.504 ;
      RECT 0.168 222.840 469.350 222.888 ;
      RECT 0.168 223.224 469.350 223.272 ;
      RECT 0.168 223.608 469.350 223.656 ;
      RECT 0.168 223.992 469.350 224.040 ;
      RECT 0.168 224.376 469.350 224.424 ;
      RECT 0.168 224.760 469.350 224.808 ;
      RECT 0.168 225.144 469.350 225.192 ;
      RECT 0.168 225.528 469.350 225.576 ;
      RECT 0.168 225.912 469.350 225.960 ;
      RECT 0.168 226.296 469.350 226.344 ;
      RECT 0.168 226.680 469.350 226.728 ;
      RECT 0.168 227.064 469.350 227.112 ;
      RECT 0.168 227.448 469.350 227.496 ;
      RECT 0.168 227.832 469.350 227.880 ;
      RECT 0.168 228.216 469.350 228.264 ;
      RECT 0.168 228.600 469.350 228.648 ;
      RECT 0.168 228.984 469.350 229.032 ;
      RECT 0.168 229.368 469.350 229.416 ;
      RECT 0.168 229.752 469.350 229.800 ;
      RECT 0.168 230.136 469.350 230.184 ;
      RECT 0.168 230.520 469.350 230.568 ;
      RECT 0.168 230.904 469.350 230.952 ;
      RECT 0.168 231.288 469.350 231.336 ;
      RECT 0.168 231.672 469.350 231.720 ;
      RECT 0.168 232.056 469.350 232.104 ;
      RECT 0.168 232.440 469.350 232.488 ;
      RECT 0.168 232.824 469.350 232.872 ;
      RECT 0.168 233.208 469.350 233.256 ;
      RECT 0.168 233.592 469.350 233.640 ;
      RECT 0.168 233.976 469.350 234.024 ;
      RECT 0.168 234.360 469.350 234.408 ;
      RECT 0.168 234.744 469.350 234.792 ;
      RECT 0.168 235.128 469.350 235.176 ;
      RECT 0.168 235.512 469.350 235.560 ;
      RECT 0.168 235.896 469.350 235.944 ;
      RECT 0.168 236.280 469.350 236.328 ;
      RECT 0.168 236.664 469.350 236.712 ;
      RECT 0.168 237.048 469.350 237.096 ;
      RECT 0.168 237.432 469.350 237.480 ;
      RECT 0.168 237.816 469.350 237.864 ;
      RECT 0.168 238.200 469.350 238.248 ;
      RECT 0.168 238.584 469.350 238.632 ;
      RECT 0.168 238.968 469.350 239.016 ;
      RECT 0.168 239.352 469.350 239.400 ;
      RECT 0.168 239.736 469.350 239.784 ;
      RECT 0.168 240.120 469.350 240.168 ;
      RECT 0.168 240.504 469.350 240.552 ;
      RECT 0.168 240.888 469.350 240.936 ;
      RECT 0.168 241.272 469.350 241.320 ;
      RECT 0.168 241.656 469.350 241.704 ;
      RECT 0.168 242.040 469.350 242.088 ;
      RECT 0.168 242.424 469.350 242.472 ;
      RECT 0.168 242.808 469.350 242.856 ;
      RECT 0.168 243.192 469.350 243.240 ;
      RECT 0.168 243.576 469.350 243.624 ;
      RECT 0.168 243.960 469.350 244.008 ;
      RECT 0.168 244.344 469.350 244.392 ;
      RECT 0.168 244.728 469.350 244.776 ;
      RECT 0.168 245.112 469.350 245.160 ;
      RECT 0.168 245.496 469.350 245.544 ;
      RECT 0.168 245.880 469.350 245.928 ;
      RECT 0.168 246.264 469.350 246.312 ;
      RECT 0.168 246.648 469.350 246.696 ;
      RECT 0.168 247.032 469.350 247.080 ;
      RECT 0.168 247.416 469.350 247.464 ;
      RECT 0.168 247.800 469.350 247.848 ;
      RECT 0.168 248.184 469.350 248.232 ;
      RECT 0.168 248.568 469.350 248.616 ;
      RECT 0.168 248.952 469.350 249.000 ;
      RECT 0.168 249.336 469.350 249.384 ;
      RECT 0.168 249.720 469.350 249.768 ;
      RECT 0.168 250.104 469.350 250.152 ;
      RECT 0.168 250.488 469.350 250.536 ;
      RECT 0.168 250.872 469.350 250.920 ;
      RECT 0.168 251.256 469.350 251.304 ;
      RECT 0.168 251.640 469.350 251.688 ;
      RECT 0.168 252.024 469.350 252.072 ;
      RECT 0.168 252.408 469.350 252.456 ;
      RECT 0.168 252.792 469.350 252.840 ;
      RECT 0.168 253.176 469.350 253.224 ;
      RECT 0.168 253.560 469.350 253.608 ;
      RECT 0.168 253.944 469.350 253.992 ;
      RECT 0.168 254.328 469.350 254.376 ;
      RECT 0.168 254.712 469.350 254.760 ;
      RECT 0.168 255.096 469.350 255.144 ;
      RECT 0.168 255.480 469.350 255.528 ;
      RECT 0.168 255.864 469.350 255.912 ;
      RECT 0.168 256.248 469.350 256.296 ;
      RECT 0.168 256.632 469.350 256.680 ;
      RECT 0.168 257.016 469.350 257.064 ;
      RECT 0.168 257.400 469.350 257.448 ;
      RECT 0.168 257.784 469.350 257.832 ;
      RECT 0.168 258.168 469.350 258.216 ;
      RECT 0.168 258.552 469.350 258.600 ;
      RECT 0.168 258.936 469.350 258.984 ;
      RECT 0.168 259.320 469.350 259.368 ;
      RECT 0.168 259.704 469.350 259.752 ;
      RECT 0.168 260.088 469.350 260.136 ;
      RECT 0.168 260.472 469.350 260.520 ;
      RECT 0.168 260.856 469.350 260.904 ;
      RECT 0.168 261.240 469.350 261.288 ;
      RECT 0.168 261.624 469.350 261.672 ;
      RECT 0.168 262.008 469.350 262.056 ;
      RECT 0.168 262.392 469.350 262.440 ;
      RECT 0.168 262.776 469.350 262.824 ;
      RECT 0.168 263.160 469.350 263.208 ;
      RECT 0.168 263.544 469.350 263.592 ;
      RECT 0.168 263.928 469.350 263.976 ;
      RECT 0.168 264.312 469.350 264.360 ;
      RECT 0.168 264.696 469.350 264.744 ;
      RECT 0.168 265.080 469.350 265.128 ;
      RECT 0.168 265.464 469.350 265.512 ;
      RECT 0.168 265.848 469.350 265.896 ;
      RECT 0.168 266.232 469.350 266.280 ;
      RECT 0.168 266.616 469.350 266.664 ;
      RECT 0.168 267.000 469.350 267.048 ;
      RECT 0.168 267.384 469.350 267.432 ;
      RECT 0.168 267.768 469.350 267.816 ;
      RECT 0.168 268.152 469.350 268.200 ;
      RECT 0.168 268.536 469.350 268.584 ;
      RECT 0.168 268.920 469.350 268.968 ;
      RECT 0.168 269.304 469.350 269.352 ;
      RECT 0.168 269.688 469.350 269.736 ;
      RECT 0.168 270.072 469.350 270.120 ;
      RECT 0.168 270.456 469.350 270.504 ;
      RECT 0.168 270.840 469.350 270.888 ;
      RECT 0.168 271.224 469.350 271.272 ;
      RECT 0.168 271.608 469.350 271.656 ;
      RECT 0.168 271.992 469.350 272.040 ;
      RECT 0.168 272.376 469.350 272.424 ;
      RECT 0.168 272.760 469.350 272.808 ;
      RECT 0.168 273.144 469.350 273.192 ;
      RECT 0.168 273.528 469.350 273.576 ;
      RECT 0.168 273.912 469.350 273.960 ;
      RECT 0.168 274.296 469.350 274.344 ;
      RECT 0.168 274.680 469.350 274.728 ;
      RECT 0.168 275.064 469.350 275.112 ;
      RECT 0.168 275.448 469.350 275.496 ;
      RECT 0.168 275.832 469.350 275.880 ;
      RECT 0.168 276.216 469.350 276.264 ;
      RECT 0.168 276.600 469.350 276.648 ;
      RECT 0.168 276.984 469.350 277.032 ;
      RECT 0.168 277.368 469.350 277.416 ;
      RECT 0.168 277.752 469.350 277.800 ;
      RECT 0.168 278.136 469.350 278.184 ;
      RECT 0.168 278.520 469.350 278.568 ;
      RECT 0.168 278.904 469.350 278.952 ;
      RECT 0.168 279.288 469.350 279.336 ;
      RECT 0.168 279.672 469.350 279.720 ;
      RECT 0.168 280.056 469.350 280.104 ;
      RECT 0.168 280.440 469.350 280.488 ;
      RECT 0.168 280.824 469.350 280.872 ;
      RECT 0.168 281.208 469.350 281.256 ;
      RECT 0.168 281.592 469.350 281.640 ;
      RECT 0.168 281.976 469.350 282.024 ;
      RECT 0.168 282.360 469.350 282.408 ;
      RECT 0.168 282.744 469.350 282.792 ;
      RECT 0.168 283.128 469.350 283.176 ;
      RECT 0.168 283.512 469.350 283.560 ;
      RECT 0.168 283.896 469.350 283.944 ;
      RECT 0.168 284.280 469.350 284.328 ;
      RECT 0.168 284.664 469.350 284.712 ;
      RECT 0.168 285.048 469.350 285.096 ;
      RECT 0.168 285.432 469.350 285.480 ;
      RECT 0.168 285.816 469.350 285.864 ;
      RECT 0.168 286.200 469.350 286.248 ;
      RECT 0.168 286.584 469.350 286.632 ;
      RECT 0.168 286.968 469.350 287.016 ;
      RECT 0.168 287.352 469.350 287.400 ;
      RECT 0.168 287.736 469.350 287.784 ;
      RECT 0.168 288.120 469.350 288.168 ;
      RECT 0.168 288.504 469.350 288.552 ;
      RECT 0.168 288.888 469.350 288.936 ;
      RECT 0.168 289.272 469.350 289.320 ;
      RECT 0.168 289.656 469.350 289.704 ;
      RECT 0.168 290.040 469.350 290.088 ;
      RECT 0.168 290.424 469.350 290.472 ;
      RECT 0.168 290.808 469.350 290.856 ;
      RECT 0.168 291.192 469.350 291.240 ;
      RECT 0.168 291.576 469.350 291.624 ;
      RECT 0.168 291.960 469.350 292.008 ;
      RECT 0.168 292.344 469.350 292.392 ;
      RECT 0.168 292.728 469.350 292.776 ;
      RECT 0.168 293.112 469.350 293.160 ;
    END
  END VSS
  PIN VDD
    DIRECTION INOUT ;
    USE POWER ;
    PORT
      LAYER M4 ;
      RECT 0.168 0.312 469.350 0.360 ;
      RECT 0.168 0.696 469.350 0.744 ;
      RECT 0.168 1.080 469.350 1.128 ;
      RECT 0.168 1.464 469.350 1.512 ;
      RECT 0.168 1.848 469.350 1.896 ;
      RECT 0.168 2.232 469.350 2.280 ;
      RECT 0.168 2.616 469.350 2.664 ;
      RECT 0.168 3.000 469.350 3.048 ;
      RECT 0.168 3.384 469.350 3.432 ;
      RECT 0.168 3.768 469.350 3.816 ;
      RECT 0.168 4.152 469.350 4.200 ;
      RECT 0.168 4.536 469.350 4.584 ;
      RECT 0.168 4.920 469.350 4.968 ;
      RECT 0.168 5.304 469.350 5.352 ;
      RECT 0.168 5.688 469.350 5.736 ;
      RECT 0.168 6.072 469.350 6.120 ;
      RECT 0.168 6.456 469.350 6.504 ;
      RECT 0.168 6.840 469.350 6.888 ;
      RECT 0.168 7.224 469.350 7.272 ;
      RECT 0.168 7.608 469.350 7.656 ;
      RECT 0.168 7.992 469.350 8.040 ;
      RECT 0.168 8.376 469.350 8.424 ;
      RECT 0.168 8.760 469.350 8.808 ;
      RECT 0.168 9.144 469.350 9.192 ;
      RECT 0.168 9.528 469.350 9.576 ;
      RECT 0.168 9.912 469.350 9.960 ;
      RECT 0.168 10.296 469.350 10.344 ;
      RECT 0.168 10.680 469.350 10.728 ;
      RECT 0.168 11.064 469.350 11.112 ;
      RECT 0.168 11.448 469.350 11.496 ;
      RECT 0.168 11.832 469.350 11.880 ;
      RECT 0.168 12.216 469.350 12.264 ;
      RECT 0.168 12.600 469.350 12.648 ;
      RECT 0.168 12.984 469.350 13.032 ;
      RECT 0.168 13.368 469.350 13.416 ;
      RECT 0.168 13.752 469.350 13.800 ;
      RECT 0.168 14.136 469.350 14.184 ;
      RECT 0.168 14.520 469.350 14.568 ;
      RECT 0.168 14.904 469.350 14.952 ;
      RECT 0.168 15.288 469.350 15.336 ;
      RECT 0.168 15.672 469.350 15.720 ;
      RECT 0.168 16.056 469.350 16.104 ;
      RECT 0.168 16.440 469.350 16.488 ;
      RECT 0.168 16.824 469.350 16.872 ;
      RECT 0.168 17.208 469.350 17.256 ;
      RECT 0.168 17.592 469.350 17.640 ;
      RECT 0.168 17.976 469.350 18.024 ;
      RECT 0.168 18.360 469.350 18.408 ;
      RECT 0.168 18.744 469.350 18.792 ;
      RECT 0.168 19.128 469.350 19.176 ;
      RECT 0.168 19.512 469.350 19.560 ;
      RECT 0.168 19.896 469.350 19.944 ;
      RECT 0.168 20.280 469.350 20.328 ;
      RECT 0.168 20.664 469.350 20.712 ;
      RECT 0.168 21.048 469.350 21.096 ;
      RECT 0.168 21.432 469.350 21.480 ;
      RECT 0.168 21.816 469.350 21.864 ;
      RECT 0.168 22.200 469.350 22.248 ;
      RECT 0.168 22.584 469.350 22.632 ;
      RECT 0.168 22.968 469.350 23.016 ;
      RECT 0.168 23.352 469.350 23.400 ;
      RECT 0.168 23.736 469.350 23.784 ;
      RECT 0.168 24.120 469.350 24.168 ;
      RECT 0.168 24.504 469.350 24.552 ;
      RECT 0.168 24.888 469.350 24.936 ;
      RECT 0.168 25.272 469.350 25.320 ;
      RECT 0.168 25.656 469.350 25.704 ;
      RECT 0.168 26.040 469.350 26.088 ;
      RECT 0.168 26.424 469.350 26.472 ;
      RECT 0.168 26.808 469.350 26.856 ;
      RECT 0.168 27.192 469.350 27.240 ;
      RECT 0.168 27.576 469.350 27.624 ;
      RECT 0.168 27.960 469.350 28.008 ;
      RECT 0.168 28.344 469.350 28.392 ;
      RECT 0.168 28.728 469.350 28.776 ;
      RECT 0.168 29.112 469.350 29.160 ;
      RECT 0.168 29.496 469.350 29.544 ;
      RECT 0.168 29.880 469.350 29.928 ;
      RECT 0.168 30.264 469.350 30.312 ;
      RECT 0.168 30.648 469.350 30.696 ;
      RECT 0.168 31.032 469.350 31.080 ;
      RECT 0.168 31.416 469.350 31.464 ;
      RECT 0.168 31.800 469.350 31.848 ;
      RECT 0.168 32.184 469.350 32.232 ;
      RECT 0.168 32.568 469.350 32.616 ;
      RECT 0.168 32.952 469.350 33.000 ;
      RECT 0.168 33.336 469.350 33.384 ;
      RECT 0.168 33.720 469.350 33.768 ;
      RECT 0.168 34.104 469.350 34.152 ;
      RECT 0.168 34.488 469.350 34.536 ;
      RECT 0.168 34.872 469.350 34.920 ;
      RECT 0.168 35.256 469.350 35.304 ;
      RECT 0.168 35.640 469.350 35.688 ;
      RECT 0.168 36.024 469.350 36.072 ;
      RECT 0.168 36.408 469.350 36.456 ;
      RECT 0.168 36.792 469.350 36.840 ;
      RECT 0.168 37.176 469.350 37.224 ;
      RECT 0.168 37.560 469.350 37.608 ;
      RECT 0.168 37.944 469.350 37.992 ;
      RECT 0.168 38.328 469.350 38.376 ;
      RECT 0.168 38.712 469.350 38.760 ;
      RECT 0.168 39.096 469.350 39.144 ;
      RECT 0.168 39.480 469.350 39.528 ;
      RECT 0.168 39.864 469.350 39.912 ;
      RECT 0.168 40.248 469.350 40.296 ;
      RECT 0.168 40.632 469.350 40.680 ;
      RECT 0.168 41.016 469.350 41.064 ;
      RECT 0.168 41.400 469.350 41.448 ;
      RECT 0.168 41.784 469.350 41.832 ;
      RECT 0.168 42.168 469.350 42.216 ;
      RECT 0.168 42.552 469.350 42.600 ;
      RECT 0.168 42.936 469.350 42.984 ;
      RECT 0.168 43.320 469.350 43.368 ;
      RECT 0.168 43.704 469.350 43.752 ;
      RECT 0.168 44.088 469.350 44.136 ;
      RECT 0.168 44.472 469.350 44.520 ;
      RECT 0.168 44.856 469.350 44.904 ;
      RECT 0.168 45.240 469.350 45.288 ;
      RECT 0.168 45.624 469.350 45.672 ;
      RECT 0.168 46.008 469.350 46.056 ;
      RECT 0.168 46.392 469.350 46.440 ;
      RECT 0.168 46.776 469.350 46.824 ;
      RECT 0.168 47.160 469.350 47.208 ;
      RECT 0.168 47.544 469.350 47.592 ;
      RECT 0.168 47.928 469.350 47.976 ;
      RECT 0.168 48.312 469.350 48.360 ;
      RECT 0.168 48.696 469.350 48.744 ;
      RECT 0.168 49.080 469.350 49.128 ;
      RECT 0.168 49.464 469.350 49.512 ;
      RECT 0.168 49.848 469.350 49.896 ;
      RECT 0.168 50.232 469.350 50.280 ;
      RECT 0.168 50.616 469.350 50.664 ;
      RECT 0.168 51.000 469.350 51.048 ;
      RECT 0.168 51.384 469.350 51.432 ;
      RECT 0.168 51.768 469.350 51.816 ;
      RECT 0.168 52.152 469.350 52.200 ;
      RECT 0.168 52.536 469.350 52.584 ;
      RECT 0.168 52.920 469.350 52.968 ;
      RECT 0.168 53.304 469.350 53.352 ;
      RECT 0.168 53.688 469.350 53.736 ;
      RECT 0.168 54.072 469.350 54.120 ;
      RECT 0.168 54.456 469.350 54.504 ;
      RECT 0.168 54.840 469.350 54.888 ;
      RECT 0.168 55.224 469.350 55.272 ;
      RECT 0.168 55.608 469.350 55.656 ;
      RECT 0.168 55.992 469.350 56.040 ;
      RECT 0.168 56.376 469.350 56.424 ;
      RECT 0.168 56.760 469.350 56.808 ;
      RECT 0.168 57.144 469.350 57.192 ;
      RECT 0.168 57.528 469.350 57.576 ;
      RECT 0.168 57.912 469.350 57.960 ;
      RECT 0.168 58.296 469.350 58.344 ;
      RECT 0.168 58.680 469.350 58.728 ;
      RECT 0.168 59.064 469.350 59.112 ;
      RECT 0.168 59.448 469.350 59.496 ;
      RECT 0.168 59.832 469.350 59.880 ;
      RECT 0.168 60.216 469.350 60.264 ;
      RECT 0.168 60.600 469.350 60.648 ;
      RECT 0.168 60.984 469.350 61.032 ;
      RECT 0.168 61.368 469.350 61.416 ;
      RECT 0.168 61.752 469.350 61.800 ;
      RECT 0.168 62.136 469.350 62.184 ;
      RECT 0.168 62.520 469.350 62.568 ;
      RECT 0.168 62.904 469.350 62.952 ;
      RECT 0.168 63.288 469.350 63.336 ;
      RECT 0.168 63.672 469.350 63.720 ;
      RECT 0.168 64.056 469.350 64.104 ;
      RECT 0.168 64.440 469.350 64.488 ;
      RECT 0.168 64.824 469.350 64.872 ;
      RECT 0.168 65.208 469.350 65.256 ;
      RECT 0.168 65.592 469.350 65.640 ;
      RECT 0.168 65.976 469.350 66.024 ;
      RECT 0.168 66.360 469.350 66.408 ;
      RECT 0.168 66.744 469.350 66.792 ;
      RECT 0.168 67.128 469.350 67.176 ;
      RECT 0.168 67.512 469.350 67.560 ;
      RECT 0.168 67.896 469.350 67.944 ;
      RECT 0.168 68.280 469.350 68.328 ;
      RECT 0.168 68.664 469.350 68.712 ;
      RECT 0.168 69.048 469.350 69.096 ;
      RECT 0.168 69.432 469.350 69.480 ;
      RECT 0.168 69.816 469.350 69.864 ;
      RECT 0.168 70.200 469.350 70.248 ;
      RECT 0.168 70.584 469.350 70.632 ;
      RECT 0.168 70.968 469.350 71.016 ;
      RECT 0.168 71.352 469.350 71.400 ;
      RECT 0.168 71.736 469.350 71.784 ;
      RECT 0.168 72.120 469.350 72.168 ;
      RECT 0.168 72.504 469.350 72.552 ;
      RECT 0.168 72.888 469.350 72.936 ;
      RECT 0.168 73.272 469.350 73.320 ;
      RECT 0.168 73.656 469.350 73.704 ;
      RECT 0.168 74.040 469.350 74.088 ;
      RECT 0.168 74.424 469.350 74.472 ;
      RECT 0.168 74.808 469.350 74.856 ;
      RECT 0.168 75.192 469.350 75.240 ;
      RECT 0.168 75.576 469.350 75.624 ;
      RECT 0.168 75.960 469.350 76.008 ;
      RECT 0.168 76.344 469.350 76.392 ;
      RECT 0.168 76.728 469.350 76.776 ;
      RECT 0.168 77.112 469.350 77.160 ;
      RECT 0.168 77.496 469.350 77.544 ;
      RECT 0.168 77.880 469.350 77.928 ;
      RECT 0.168 78.264 469.350 78.312 ;
      RECT 0.168 78.648 469.350 78.696 ;
      RECT 0.168 79.032 469.350 79.080 ;
      RECT 0.168 79.416 469.350 79.464 ;
      RECT 0.168 79.800 469.350 79.848 ;
      RECT 0.168 80.184 469.350 80.232 ;
      RECT 0.168 80.568 469.350 80.616 ;
      RECT 0.168 80.952 469.350 81.000 ;
      RECT 0.168 81.336 469.350 81.384 ;
      RECT 0.168 81.720 469.350 81.768 ;
      RECT 0.168 82.104 469.350 82.152 ;
      RECT 0.168 82.488 469.350 82.536 ;
      RECT 0.168 82.872 469.350 82.920 ;
      RECT 0.168 83.256 469.350 83.304 ;
      RECT 0.168 83.640 469.350 83.688 ;
      RECT 0.168 84.024 469.350 84.072 ;
      RECT 0.168 84.408 469.350 84.456 ;
      RECT 0.168 84.792 469.350 84.840 ;
      RECT 0.168 85.176 469.350 85.224 ;
      RECT 0.168 85.560 469.350 85.608 ;
      RECT 0.168 85.944 469.350 85.992 ;
      RECT 0.168 86.328 469.350 86.376 ;
      RECT 0.168 86.712 469.350 86.760 ;
      RECT 0.168 87.096 469.350 87.144 ;
      RECT 0.168 87.480 469.350 87.528 ;
      RECT 0.168 87.864 469.350 87.912 ;
      RECT 0.168 88.248 469.350 88.296 ;
      RECT 0.168 88.632 469.350 88.680 ;
      RECT 0.168 89.016 469.350 89.064 ;
      RECT 0.168 89.400 469.350 89.448 ;
      RECT 0.168 89.784 469.350 89.832 ;
      RECT 0.168 90.168 469.350 90.216 ;
      RECT 0.168 90.552 469.350 90.600 ;
      RECT 0.168 90.936 469.350 90.984 ;
      RECT 0.168 91.320 469.350 91.368 ;
      RECT 0.168 91.704 469.350 91.752 ;
      RECT 0.168 92.088 469.350 92.136 ;
      RECT 0.168 92.472 469.350 92.520 ;
      RECT 0.168 92.856 469.350 92.904 ;
      RECT 0.168 93.240 469.350 93.288 ;
      RECT 0.168 93.624 469.350 93.672 ;
      RECT 0.168 94.008 469.350 94.056 ;
      RECT 0.168 94.392 469.350 94.440 ;
      RECT 0.168 94.776 469.350 94.824 ;
      RECT 0.168 95.160 469.350 95.208 ;
      RECT 0.168 95.544 469.350 95.592 ;
      RECT 0.168 95.928 469.350 95.976 ;
      RECT 0.168 96.312 469.350 96.360 ;
      RECT 0.168 96.696 469.350 96.744 ;
      RECT 0.168 97.080 469.350 97.128 ;
      RECT 0.168 97.464 469.350 97.512 ;
      RECT 0.168 97.848 469.350 97.896 ;
      RECT 0.168 98.232 469.350 98.280 ;
      RECT 0.168 98.616 469.350 98.664 ;
      RECT 0.168 99.000 469.350 99.048 ;
      RECT 0.168 99.384 469.350 99.432 ;
      RECT 0.168 99.768 469.350 99.816 ;
      RECT 0.168 100.152 469.350 100.200 ;
      RECT 0.168 100.536 469.350 100.584 ;
      RECT 0.168 100.920 469.350 100.968 ;
      RECT 0.168 101.304 469.350 101.352 ;
      RECT 0.168 101.688 469.350 101.736 ;
      RECT 0.168 102.072 469.350 102.120 ;
      RECT 0.168 102.456 469.350 102.504 ;
      RECT 0.168 102.840 469.350 102.888 ;
      RECT 0.168 103.224 469.350 103.272 ;
      RECT 0.168 103.608 469.350 103.656 ;
      RECT 0.168 103.992 469.350 104.040 ;
      RECT 0.168 104.376 469.350 104.424 ;
      RECT 0.168 104.760 469.350 104.808 ;
      RECT 0.168 105.144 469.350 105.192 ;
      RECT 0.168 105.528 469.350 105.576 ;
      RECT 0.168 105.912 469.350 105.960 ;
      RECT 0.168 106.296 469.350 106.344 ;
      RECT 0.168 106.680 469.350 106.728 ;
      RECT 0.168 107.064 469.350 107.112 ;
      RECT 0.168 107.448 469.350 107.496 ;
      RECT 0.168 107.832 469.350 107.880 ;
      RECT 0.168 108.216 469.350 108.264 ;
      RECT 0.168 108.600 469.350 108.648 ;
      RECT 0.168 108.984 469.350 109.032 ;
      RECT 0.168 109.368 469.350 109.416 ;
      RECT 0.168 109.752 469.350 109.800 ;
      RECT 0.168 110.136 469.350 110.184 ;
      RECT 0.168 110.520 469.350 110.568 ;
      RECT 0.168 110.904 469.350 110.952 ;
      RECT 0.168 111.288 469.350 111.336 ;
      RECT 0.168 111.672 469.350 111.720 ;
      RECT 0.168 112.056 469.350 112.104 ;
      RECT 0.168 112.440 469.350 112.488 ;
      RECT 0.168 112.824 469.350 112.872 ;
      RECT 0.168 113.208 469.350 113.256 ;
      RECT 0.168 113.592 469.350 113.640 ;
      RECT 0.168 113.976 469.350 114.024 ;
      RECT 0.168 114.360 469.350 114.408 ;
      RECT 0.168 114.744 469.350 114.792 ;
      RECT 0.168 115.128 469.350 115.176 ;
      RECT 0.168 115.512 469.350 115.560 ;
      RECT 0.168 115.896 469.350 115.944 ;
      RECT 0.168 116.280 469.350 116.328 ;
      RECT 0.168 116.664 469.350 116.712 ;
      RECT 0.168 117.048 469.350 117.096 ;
      RECT 0.168 117.432 469.350 117.480 ;
      RECT 0.168 117.816 469.350 117.864 ;
      RECT 0.168 118.200 469.350 118.248 ;
      RECT 0.168 118.584 469.350 118.632 ;
      RECT 0.168 118.968 469.350 119.016 ;
      RECT 0.168 119.352 469.350 119.400 ;
      RECT 0.168 119.736 469.350 119.784 ;
      RECT 0.168 120.120 469.350 120.168 ;
      RECT 0.168 120.504 469.350 120.552 ;
      RECT 0.168 120.888 469.350 120.936 ;
      RECT 0.168 121.272 469.350 121.320 ;
      RECT 0.168 121.656 469.350 121.704 ;
      RECT 0.168 122.040 469.350 122.088 ;
      RECT 0.168 122.424 469.350 122.472 ;
      RECT 0.168 122.808 469.350 122.856 ;
      RECT 0.168 123.192 469.350 123.240 ;
      RECT 0.168 123.576 469.350 123.624 ;
      RECT 0.168 123.960 469.350 124.008 ;
      RECT 0.168 124.344 469.350 124.392 ;
      RECT 0.168 124.728 469.350 124.776 ;
      RECT 0.168 125.112 469.350 125.160 ;
      RECT 0.168 125.496 469.350 125.544 ;
      RECT 0.168 125.880 469.350 125.928 ;
      RECT 0.168 126.264 469.350 126.312 ;
      RECT 0.168 126.648 469.350 126.696 ;
      RECT 0.168 127.032 469.350 127.080 ;
      RECT 0.168 127.416 469.350 127.464 ;
      RECT 0.168 127.800 469.350 127.848 ;
      RECT 0.168 128.184 469.350 128.232 ;
      RECT 0.168 128.568 469.350 128.616 ;
      RECT 0.168 128.952 469.350 129.000 ;
      RECT 0.168 129.336 469.350 129.384 ;
      RECT 0.168 129.720 469.350 129.768 ;
      RECT 0.168 130.104 469.350 130.152 ;
      RECT 0.168 130.488 469.350 130.536 ;
      RECT 0.168 130.872 469.350 130.920 ;
      RECT 0.168 131.256 469.350 131.304 ;
      RECT 0.168 131.640 469.350 131.688 ;
      RECT 0.168 132.024 469.350 132.072 ;
      RECT 0.168 132.408 469.350 132.456 ;
      RECT 0.168 132.792 469.350 132.840 ;
      RECT 0.168 133.176 469.350 133.224 ;
      RECT 0.168 133.560 469.350 133.608 ;
      RECT 0.168 133.944 469.350 133.992 ;
      RECT 0.168 134.328 469.350 134.376 ;
      RECT 0.168 134.712 469.350 134.760 ;
      RECT 0.168 135.096 469.350 135.144 ;
      RECT 0.168 135.480 469.350 135.528 ;
      RECT 0.168 135.864 469.350 135.912 ;
      RECT 0.168 136.248 469.350 136.296 ;
      RECT 0.168 136.632 469.350 136.680 ;
      RECT 0.168 137.016 469.350 137.064 ;
      RECT 0.168 137.400 469.350 137.448 ;
      RECT 0.168 137.784 469.350 137.832 ;
      RECT 0.168 138.168 469.350 138.216 ;
      RECT 0.168 138.552 469.350 138.600 ;
      RECT 0.168 138.936 469.350 138.984 ;
      RECT 0.168 139.320 469.350 139.368 ;
      RECT 0.168 139.704 469.350 139.752 ;
      RECT 0.168 140.088 469.350 140.136 ;
      RECT 0.168 140.472 469.350 140.520 ;
      RECT 0.168 140.856 469.350 140.904 ;
      RECT 0.168 141.240 469.350 141.288 ;
      RECT 0.168 141.624 469.350 141.672 ;
      RECT 0.168 142.008 469.350 142.056 ;
      RECT 0.168 142.392 469.350 142.440 ;
      RECT 0.168 142.776 469.350 142.824 ;
      RECT 0.168 143.160 469.350 143.208 ;
      RECT 0.168 143.544 469.350 143.592 ;
      RECT 0.168 143.928 469.350 143.976 ;
      RECT 0.168 144.312 469.350 144.360 ;
      RECT 0.168 144.696 469.350 144.744 ;
      RECT 0.168 145.080 469.350 145.128 ;
      RECT 0.168 145.464 469.350 145.512 ;
      RECT 0.168 145.848 469.350 145.896 ;
      RECT 0.168 146.232 469.350 146.280 ;
      RECT 0.168 146.616 469.350 146.664 ;
      RECT 0.168 147.000 469.350 147.048 ;
      RECT 0.168 147.384 469.350 147.432 ;
      RECT 0.168 147.768 469.350 147.816 ;
      RECT 0.168 148.152 469.350 148.200 ;
      RECT 0.168 148.536 469.350 148.584 ;
      RECT 0.168 148.920 469.350 148.968 ;
      RECT 0.168 149.304 469.350 149.352 ;
      RECT 0.168 149.688 469.350 149.736 ;
      RECT 0.168 150.072 469.350 150.120 ;
      RECT 0.168 150.456 469.350 150.504 ;
      RECT 0.168 150.840 469.350 150.888 ;
      RECT 0.168 151.224 469.350 151.272 ;
      RECT 0.168 151.608 469.350 151.656 ;
      RECT 0.168 151.992 469.350 152.040 ;
      RECT 0.168 152.376 469.350 152.424 ;
      RECT 0.168 152.760 469.350 152.808 ;
      RECT 0.168 153.144 469.350 153.192 ;
      RECT 0.168 153.528 469.350 153.576 ;
      RECT 0.168 153.912 469.350 153.960 ;
      RECT 0.168 154.296 469.350 154.344 ;
      RECT 0.168 154.680 469.350 154.728 ;
      RECT 0.168 155.064 469.350 155.112 ;
      RECT 0.168 155.448 469.350 155.496 ;
      RECT 0.168 155.832 469.350 155.880 ;
      RECT 0.168 156.216 469.350 156.264 ;
      RECT 0.168 156.600 469.350 156.648 ;
      RECT 0.168 156.984 469.350 157.032 ;
      RECT 0.168 157.368 469.350 157.416 ;
      RECT 0.168 157.752 469.350 157.800 ;
      RECT 0.168 158.136 469.350 158.184 ;
      RECT 0.168 158.520 469.350 158.568 ;
      RECT 0.168 158.904 469.350 158.952 ;
      RECT 0.168 159.288 469.350 159.336 ;
      RECT 0.168 159.672 469.350 159.720 ;
      RECT 0.168 160.056 469.350 160.104 ;
      RECT 0.168 160.440 469.350 160.488 ;
      RECT 0.168 160.824 469.350 160.872 ;
      RECT 0.168 161.208 469.350 161.256 ;
      RECT 0.168 161.592 469.350 161.640 ;
      RECT 0.168 161.976 469.350 162.024 ;
      RECT 0.168 162.360 469.350 162.408 ;
      RECT 0.168 162.744 469.350 162.792 ;
      RECT 0.168 163.128 469.350 163.176 ;
      RECT 0.168 163.512 469.350 163.560 ;
      RECT 0.168 163.896 469.350 163.944 ;
      RECT 0.168 164.280 469.350 164.328 ;
      RECT 0.168 164.664 469.350 164.712 ;
      RECT 0.168 165.048 469.350 165.096 ;
      RECT 0.168 165.432 469.350 165.480 ;
      RECT 0.168 165.816 469.350 165.864 ;
      RECT 0.168 166.200 469.350 166.248 ;
      RECT 0.168 166.584 469.350 166.632 ;
      RECT 0.168 166.968 469.350 167.016 ;
      RECT 0.168 167.352 469.350 167.400 ;
      RECT 0.168 167.736 469.350 167.784 ;
      RECT 0.168 168.120 469.350 168.168 ;
      RECT 0.168 168.504 469.350 168.552 ;
      RECT 0.168 168.888 469.350 168.936 ;
      RECT 0.168 169.272 469.350 169.320 ;
      RECT 0.168 169.656 469.350 169.704 ;
      RECT 0.168 170.040 469.350 170.088 ;
      RECT 0.168 170.424 469.350 170.472 ;
      RECT 0.168 170.808 469.350 170.856 ;
      RECT 0.168 171.192 469.350 171.240 ;
      RECT 0.168 171.576 469.350 171.624 ;
      RECT 0.168 171.960 469.350 172.008 ;
      RECT 0.168 172.344 469.350 172.392 ;
      RECT 0.168 172.728 469.350 172.776 ;
      RECT 0.168 173.112 469.350 173.160 ;
      RECT 0.168 173.496 469.350 173.544 ;
      RECT 0.168 173.880 469.350 173.928 ;
      RECT 0.168 174.264 469.350 174.312 ;
      RECT 0.168 174.648 469.350 174.696 ;
      RECT 0.168 175.032 469.350 175.080 ;
      RECT 0.168 175.416 469.350 175.464 ;
      RECT 0.168 175.800 469.350 175.848 ;
      RECT 0.168 176.184 469.350 176.232 ;
      RECT 0.168 176.568 469.350 176.616 ;
      RECT 0.168 176.952 469.350 177.000 ;
      RECT 0.168 177.336 469.350 177.384 ;
      RECT 0.168 177.720 469.350 177.768 ;
      RECT 0.168 178.104 469.350 178.152 ;
      RECT 0.168 178.488 469.350 178.536 ;
      RECT 0.168 178.872 469.350 178.920 ;
      RECT 0.168 179.256 469.350 179.304 ;
      RECT 0.168 179.640 469.350 179.688 ;
      RECT 0.168 180.024 469.350 180.072 ;
      RECT 0.168 180.408 469.350 180.456 ;
      RECT 0.168 180.792 469.350 180.840 ;
      RECT 0.168 181.176 469.350 181.224 ;
      RECT 0.168 181.560 469.350 181.608 ;
      RECT 0.168 181.944 469.350 181.992 ;
      RECT 0.168 182.328 469.350 182.376 ;
      RECT 0.168 182.712 469.350 182.760 ;
      RECT 0.168 183.096 469.350 183.144 ;
      RECT 0.168 183.480 469.350 183.528 ;
      RECT 0.168 183.864 469.350 183.912 ;
      RECT 0.168 184.248 469.350 184.296 ;
      RECT 0.168 184.632 469.350 184.680 ;
      RECT 0.168 185.016 469.350 185.064 ;
      RECT 0.168 185.400 469.350 185.448 ;
      RECT 0.168 185.784 469.350 185.832 ;
      RECT 0.168 186.168 469.350 186.216 ;
      RECT 0.168 186.552 469.350 186.600 ;
      RECT 0.168 186.936 469.350 186.984 ;
      RECT 0.168 187.320 469.350 187.368 ;
      RECT 0.168 187.704 469.350 187.752 ;
      RECT 0.168 188.088 469.350 188.136 ;
      RECT 0.168 188.472 469.350 188.520 ;
      RECT 0.168 188.856 469.350 188.904 ;
      RECT 0.168 189.240 469.350 189.288 ;
      RECT 0.168 189.624 469.350 189.672 ;
      RECT 0.168 190.008 469.350 190.056 ;
      RECT 0.168 190.392 469.350 190.440 ;
      RECT 0.168 190.776 469.350 190.824 ;
      RECT 0.168 191.160 469.350 191.208 ;
      RECT 0.168 191.544 469.350 191.592 ;
      RECT 0.168 191.928 469.350 191.976 ;
      RECT 0.168 192.312 469.350 192.360 ;
      RECT 0.168 192.696 469.350 192.744 ;
      RECT 0.168 193.080 469.350 193.128 ;
      RECT 0.168 193.464 469.350 193.512 ;
      RECT 0.168 193.848 469.350 193.896 ;
      RECT 0.168 194.232 469.350 194.280 ;
      RECT 0.168 194.616 469.350 194.664 ;
      RECT 0.168 195.000 469.350 195.048 ;
      RECT 0.168 195.384 469.350 195.432 ;
      RECT 0.168 195.768 469.350 195.816 ;
      RECT 0.168 196.152 469.350 196.200 ;
      RECT 0.168 196.536 469.350 196.584 ;
      RECT 0.168 196.920 469.350 196.968 ;
      RECT 0.168 197.304 469.350 197.352 ;
      RECT 0.168 197.688 469.350 197.736 ;
      RECT 0.168 198.072 469.350 198.120 ;
      RECT 0.168 198.456 469.350 198.504 ;
      RECT 0.168 198.840 469.350 198.888 ;
      RECT 0.168 199.224 469.350 199.272 ;
      RECT 0.168 199.608 469.350 199.656 ;
      RECT 0.168 199.992 469.350 200.040 ;
      RECT 0.168 200.376 469.350 200.424 ;
      RECT 0.168 200.760 469.350 200.808 ;
      RECT 0.168 201.144 469.350 201.192 ;
      RECT 0.168 201.528 469.350 201.576 ;
      RECT 0.168 201.912 469.350 201.960 ;
      RECT 0.168 202.296 469.350 202.344 ;
      RECT 0.168 202.680 469.350 202.728 ;
      RECT 0.168 203.064 469.350 203.112 ;
      RECT 0.168 203.448 469.350 203.496 ;
      RECT 0.168 203.832 469.350 203.880 ;
      RECT 0.168 204.216 469.350 204.264 ;
      RECT 0.168 204.600 469.350 204.648 ;
      RECT 0.168 204.984 469.350 205.032 ;
      RECT 0.168 205.368 469.350 205.416 ;
      RECT 0.168 205.752 469.350 205.800 ;
      RECT 0.168 206.136 469.350 206.184 ;
      RECT 0.168 206.520 469.350 206.568 ;
      RECT 0.168 206.904 469.350 206.952 ;
      RECT 0.168 207.288 469.350 207.336 ;
      RECT 0.168 207.672 469.350 207.720 ;
      RECT 0.168 208.056 469.350 208.104 ;
      RECT 0.168 208.440 469.350 208.488 ;
      RECT 0.168 208.824 469.350 208.872 ;
      RECT 0.168 209.208 469.350 209.256 ;
      RECT 0.168 209.592 469.350 209.640 ;
      RECT 0.168 209.976 469.350 210.024 ;
      RECT 0.168 210.360 469.350 210.408 ;
      RECT 0.168 210.744 469.350 210.792 ;
      RECT 0.168 211.128 469.350 211.176 ;
      RECT 0.168 211.512 469.350 211.560 ;
      RECT 0.168 211.896 469.350 211.944 ;
      RECT 0.168 212.280 469.350 212.328 ;
      RECT 0.168 212.664 469.350 212.712 ;
      RECT 0.168 213.048 469.350 213.096 ;
      RECT 0.168 213.432 469.350 213.480 ;
      RECT 0.168 213.816 469.350 213.864 ;
      RECT 0.168 214.200 469.350 214.248 ;
      RECT 0.168 214.584 469.350 214.632 ;
      RECT 0.168 214.968 469.350 215.016 ;
      RECT 0.168 215.352 469.350 215.400 ;
      RECT 0.168 215.736 469.350 215.784 ;
      RECT 0.168 216.120 469.350 216.168 ;
      RECT 0.168 216.504 469.350 216.552 ;
      RECT 0.168 216.888 469.350 216.936 ;
      RECT 0.168 217.272 469.350 217.320 ;
      RECT 0.168 217.656 469.350 217.704 ;
      RECT 0.168 218.040 469.350 218.088 ;
      RECT 0.168 218.424 469.350 218.472 ;
      RECT 0.168 218.808 469.350 218.856 ;
      RECT 0.168 219.192 469.350 219.240 ;
      RECT 0.168 219.576 469.350 219.624 ;
      RECT 0.168 219.960 469.350 220.008 ;
      RECT 0.168 220.344 469.350 220.392 ;
      RECT 0.168 220.728 469.350 220.776 ;
      RECT 0.168 221.112 469.350 221.160 ;
      RECT 0.168 221.496 469.350 221.544 ;
      RECT 0.168 221.880 469.350 221.928 ;
      RECT 0.168 222.264 469.350 222.312 ;
      RECT 0.168 222.648 469.350 222.696 ;
      RECT 0.168 223.032 469.350 223.080 ;
      RECT 0.168 223.416 469.350 223.464 ;
      RECT 0.168 223.800 469.350 223.848 ;
      RECT 0.168 224.184 469.350 224.232 ;
      RECT 0.168 224.568 469.350 224.616 ;
      RECT 0.168 224.952 469.350 225.000 ;
      RECT 0.168 225.336 469.350 225.384 ;
      RECT 0.168 225.720 469.350 225.768 ;
      RECT 0.168 226.104 469.350 226.152 ;
      RECT 0.168 226.488 469.350 226.536 ;
      RECT 0.168 226.872 469.350 226.920 ;
      RECT 0.168 227.256 469.350 227.304 ;
      RECT 0.168 227.640 469.350 227.688 ;
      RECT 0.168 228.024 469.350 228.072 ;
      RECT 0.168 228.408 469.350 228.456 ;
      RECT 0.168 228.792 469.350 228.840 ;
      RECT 0.168 229.176 469.350 229.224 ;
      RECT 0.168 229.560 469.350 229.608 ;
      RECT 0.168 229.944 469.350 229.992 ;
      RECT 0.168 230.328 469.350 230.376 ;
      RECT 0.168 230.712 469.350 230.760 ;
      RECT 0.168 231.096 469.350 231.144 ;
      RECT 0.168 231.480 469.350 231.528 ;
      RECT 0.168 231.864 469.350 231.912 ;
      RECT 0.168 232.248 469.350 232.296 ;
      RECT 0.168 232.632 469.350 232.680 ;
      RECT 0.168 233.016 469.350 233.064 ;
      RECT 0.168 233.400 469.350 233.448 ;
      RECT 0.168 233.784 469.350 233.832 ;
      RECT 0.168 234.168 469.350 234.216 ;
      RECT 0.168 234.552 469.350 234.600 ;
      RECT 0.168 234.936 469.350 234.984 ;
      RECT 0.168 235.320 469.350 235.368 ;
      RECT 0.168 235.704 469.350 235.752 ;
      RECT 0.168 236.088 469.350 236.136 ;
      RECT 0.168 236.472 469.350 236.520 ;
      RECT 0.168 236.856 469.350 236.904 ;
      RECT 0.168 237.240 469.350 237.288 ;
      RECT 0.168 237.624 469.350 237.672 ;
      RECT 0.168 238.008 469.350 238.056 ;
      RECT 0.168 238.392 469.350 238.440 ;
      RECT 0.168 238.776 469.350 238.824 ;
      RECT 0.168 239.160 469.350 239.208 ;
      RECT 0.168 239.544 469.350 239.592 ;
      RECT 0.168 239.928 469.350 239.976 ;
      RECT 0.168 240.312 469.350 240.360 ;
      RECT 0.168 240.696 469.350 240.744 ;
      RECT 0.168 241.080 469.350 241.128 ;
      RECT 0.168 241.464 469.350 241.512 ;
      RECT 0.168 241.848 469.350 241.896 ;
      RECT 0.168 242.232 469.350 242.280 ;
      RECT 0.168 242.616 469.350 242.664 ;
      RECT 0.168 243.000 469.350 243.048 ;
      RECT 0.168 243.384 469.350 243.432 ;
      RECT 0.168 243.768 469.350 243.816 ;
      RECT 0.168 244.152 469.350 244.200 ;
      RECT 0.168 244.536 469.350 244.584 ;
      RECT 0.168 244.920 469.350 244.968 ;
      RECT 0.168 245.304 469.350 245.352 ;
      RECT 0.168 245.688 469.350 245.736 ;
      RECT 0.168 246.072 469.350 246.120 ;
      RECT 0.168 246.456 469.350 246.504 ;
      RECT 0.168 246.840 469.350 246.888 ;
      RECT 0.168 247.224 469.350 247.272 ;
      RECT 0.168 247.608 469.350 247.656 ;
      RECT 0.168 247.992 469.350 248.040 ;
      RECT 0.168 248.376 469.350 248.424 ;
      RECT 0.168 248.760 469.350 248.808 ;
      RECT 0.168 249.144 469.350 249.192 ;
      RECT 0.168 249.528 469.350 249.576 ;
      RECT 0.168 249.912 469.350 249.960 ;
      RECT 0.168 250.296 469.350 250.344 ;
      RECT 0.168 250.680 469.350 250.728 ;
      RECT 0.168 251.064 469.350 251.112 ;
      RECT 0.168 251.448 469.350 251.496 ;
      RECT 0.168 251.832 469.350 251.880 ;
      RECT 0.168 252.216 469.350 252.264 ;
      RECT 0.168 252.600 469.350 252.648 ;
      RECT 0.168 252.984 469.350 253.032 ;
      RECT 0.168 253.368 469.350 253.416 ;
      RECT 0.168 253.752 469.350 253.800 ;
      RECT 0.168 254.136 469.350 254.184 ;
      RECT 0.168 254.520 469.350 254.568 ;
      RECT 0.168 254.904 469.350 254.952 ;
      RECT 0.168 255.288 469.350 255.336 ;
      RECT 0.168 255.672 469.350 255.720 ;
      RECT 0.168 256.056 469.350 256.104 ;
      RECT 0.168 256.440 469.350 256.488 ;
      RECT 0.168 256.824 469.350 256.872 ;
      RECT 0.168 257.208 469.350 257.256 ;
      RECT 0.168 257.592 469.350 257.640 ;
      RECT 0.168 257.976 469.350 258.024 ;
      RECT 0.168 258.360 469.350 258.408 ;
      RECT 0.168 258.744 469.350 258.792 ;
      RECT 0.168 259.128 469.350 259.176 ;
      RECT 0.168 259.512 469.350 259.560 ;
      RECT 0.168 259.896 469.350 259.944 ;
      RECT 0.168 260.280 469.350 260.328 ;
      RECT 0.168 260.664 469.350 260.712 ;
      RECT 0.168 261.048 469.350 261.096 ;
      RECT 0.168 261.432 469.350 261.480 ;
      RECT 0.168 261.816 469.350 261.864 ;
      RECT 0.168 262.200 469.350 262.248 ;
      RECT 0.168 262.584 469.350 262.632 ;
      RECT 0.168 262.968 469.350 263.016 ;
      RECT 0.168 263.352 469.350 263.400 ;
      RECT 0.168 263.736 469.350 263.784 ;
      RECT 0.168 264.120 469.350 264.168 ;
      RECT 0.168 264.504 469.350 264.552 ;
      RECT 0.168 264.888 469.350 264.936 ;
      RECT 0.168 265.272 469.350 265.320 ;
      RECT 0.168 265.656 469.350 265.704 ;
      RECT 0.168 266.040 469.350 266.088 ;
      RECT 0.168 266.424 469.350 266.472 ;
      RECT 0.168 266.808 469.350 266.856 ;
      RECT 0.168 267.192 469.350 267.240 ;
      RECT 0.168 267.576 469.350 267.624 ;
      RECT 0.168 267.960 469.350 268.008 ;
      RECT 0.168 268.344 469.350 268.392 ;
      RECT 0.168 268.728 469.350 268.776 ;
      RECT 0.168 269.112 469.350 269.160 ;
      RECT 0.168 269.496 469.350 269.544 ;
      RECT 0.168 269.880 469.350 269.928 ;
      RECT 0.168 270.264 469.350 270.312 ;
      RECT 0.168 270.648 469.350 270.696 ;
      RECT 0.168 271.032 469.350 271.080 ;
      RECT 0.168 271.416 469.350 271.464 ;
      RECT 0.168 271.800 469.350 271.848 ;
      RECT 0.168 272.184 469.350 272.232 ;
      RECT 0.168 272.568 469.350 272.616 ;
      RECT 0.168 272.952 469.350 273.000 ;
      RECT 0.168 273.336 469.350 273.384 ;
      RECT 0.168 273.720 469.350 273.768 ;
      RECT 0.168 274.104 469.350 274.152 ;
      RECT 0.168 274.488 469.350 274.536 ;
      RECT 0.168 274.872 469.350 274.920 ;
      RECT 0.168 275.256 469.350 275.304 ;
      RECT 0.168 275.640 469.350 275.688 ;
      RECT 0.168 276.024 469.350 276.072 ;
      RECT 0.168 276.408 469.350 276.456 ;
      RECT 0.168 276.792 469.350 276.840 ;
      RECT 0.168 277.176 469.350 277.224 ;
      RECT 0.168 277.560 469.350 277.608 ;
      RECT 0.168 277.944 469.350 277.992 ;
      RECT 0.168 278.328 469.350 278.376 ;
      RECT 0.168 278.712 469.350 278.760 ;
      RECT 0.168 279.096 469.350 279.144 ;
      RECT 0.168 279.480 469.350 279.528 ;
      RECT 0.168 279.864 469.350 279.912 ;
      RECT 0.168 280.248 469.350 280.296 ;
      RECT 0.168 280.632 469.350 280.680 ;
      RECT 0.168 281.016 469.350 281.064 ;
      RECT 0.168 281.400 469.350 281.448 ;
      RECT 0.168 281.784 469.350 281.832 ;
      RECT 0.168 282.168 469.350 282.216 ;
      RECT 0.168 282.552 469.350 282.600 ;
      RECT 0.168 282.936 469.350 282.984 ;
      RECT 0.168 283.320 469.350 283.368 ;
      RECT 0.168 283.704 469.350 283.752 ;
      RECT 0.168 284.088 469.350 284.136 ;
      RECT 0.168 284.472 469.350 284.520 ;
      RECT 0.168 284.856 469.350 284.904 ;
      RECT 0.168 285.240 469.350 285.288 ;
      RECT 0.168 285.624 469.350 285.672 ;
      RECT 0.168 286.008 469.350 286.056 ;
      RECT 0.168 286.392 469.350 286.440 ;
      RECT 0.168 286.776 469.350 286.824 ;
      RECT 0.168 287.160 469.350 287.208 ;
      RECT 0.168 287.544 469.350 287.592 ;
      RECT 0.168 287.928 469.350 287.976 ;
      RECT 0.168 288.312 469.350 288.360 ;
      RECT 0.168 288.696 469.350 288.744 ;
      RECT 0.168 289.080 469.350 289.128 ;
      RECT 0.168 289.464 469.350 289.512 ;
      RECT 0.168 289.848 469.350 289.896 ;
      RECT 0.168 290.232 469.350 290.280 ;
      RECT 0.168 290.616 469.350 290.664 ;
      RECT 0.168 291.000 469.350 291.048 ;
      RECT 0.168 291.384 469.350 291.432 ;
      RECT 0.168 291.768 469.350 291.816 ;
      RECT 0.168 292.152 469.350 292.200 ;
      RECT 0.168 292.536 469.350 292.584 ;
      RECT 0.168 292.920 469.350 292.968 ;
    END
  END VDD
  OBS
    LAYER M1 ;
    RECT 0 0 469.518 293.328 ;
    LAYER M2 ;
    RECT 0 0 469.518 293.328 ;
    LAYER M3 ;
    RECT 0 0 469.518 293.328 ;
    LAYER M4 ;
    RECT 0 0 469.518 293.328 ;
  END
END fakeram_w64_l16384

END LIBRARY
